VERSION 5.7 ;
BUSBITCHARS "[]" ;
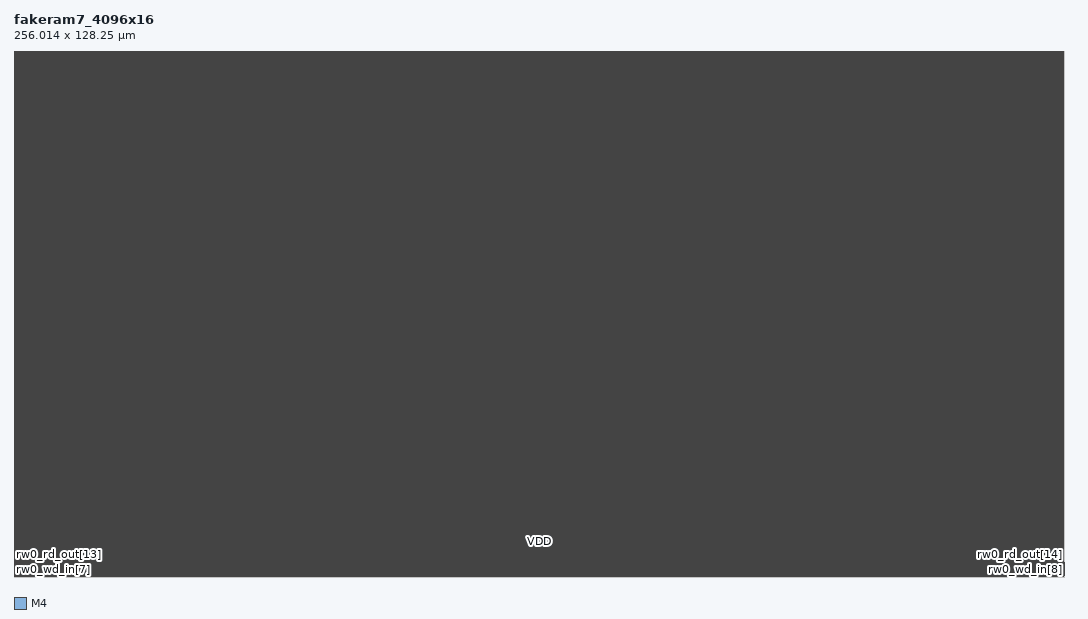
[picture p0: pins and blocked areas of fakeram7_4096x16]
MACRO fakeram7_4096x16
  FOREIGN fakeram7_4096x16 0 0 ;
  SYMMETRY X Y R90 ;
  SIZE 256.014 BY 128.250 ;
  CLASS BLOCK ;
  PIN rw0_clk
    DIRECTION INPUT ;
    USE SIGNAL ;
    SHAPE ABUTMENT ;
    PORT
      LAYER M4 ;
      RECT 0.000 0.276 0.072 0.300 ;
    END
  END rw0_clk
  PIN rw0_ce_in
    DIRECTION INPUT ;
    USE SIGNAL ;
    SHAPE ABUTMENT ;
    PORT
      LAYER M4 ;
      RECT 255.942 0.276 256.014 0.300 ;
    END
  END rw0_ce_in
  PIN rw0_we_in
    DIRECTION INPUT ;
    USE SIGNAL ;
    SHAPE ABUTMENT ;
    PORT
      LAYER M4 ;
      RECT 0.000 0.420 0.072 0.444 ;
    END
  END rw0_we_in
  PIN rw0_addr_in[0]
    DIRECTION INPUT ;
    USE SIGNAL ;
    SHAPE ABUTMENT ;
    PORT
      LAYER M4 ;
      RECT 255.942 0.420 256.014 0.444 ;
    END
  END rw0_addr_in[0]
  PIN rw0_addr_in[1]
    DIRECTION INPUT ;
    USE SIGNAL ;
    SHAPE ABUTMENT ;
    PORT
      LAYER M4 ;
      RECT 0.000 0.564 0.072 0.588 ;
    END
  END rw0_addr_in[1]
  PIN rw0_addr_in[2]
    DIRECTION INPUT ;
    USE SIGNAL ;
    SHAPE ABUTMENT ;
    PORT
      LAYER M4 ;
      RECT 255.942 0.564 256.014 0.588 ;
    END
  END rw0_addr_in[2]
  PIN rw0_addr_in[3]
    DIRECTION INPUT ;
    USE SIGNAL ;
    SHAPE ABUTMENT ;
    PORT
      LAYER M4 ;
      RECT 0.000 0.708 0.072 0.732 ;
    END
  END rw0_addr_in[3]
  PIN rw0_addr_in[4]
    DIRECTION INPUT ;
    USE SIGNAL ;
    SHAPE ABUTMENT ;
    PORT
      LAYER M4 ;
      RECT 255.942 0.708 256.014 0.732 ;
    END
  END rw0_addr_in[4]
  PIN rw0_addr_in[5]
    DIRECTION INPUT ;
    USE SIGNAL ;
    SHAPE ABUTMENT ;
    PORT
      LAYER M4 ;
      RECT 0.000 0.852 0.072 0.876 ;
    END
  END rw0_addr_in[5]
  PIN rw0_addr_in[6]
    DIRECTION INPUT ;
    USE SIGNAL ;
    SHAPE ABUTMENT ;
    PORT
      LAYER M4 ;
      RECT 255.942 0.852 256.014 0.876 ;
    END
  END rw0_addr_in[6]
  PIN rw0_addr_in[7]
    DIRECTION INPUT ;
    USE SIGNAL ;
    SHAPE ABUTMENT ;
    PORT
      LAYER M4 ;
      RECT 0.000 0.996 0.072 1.020 ;
    END
  END rw0_addr_in[7]
  PIN rw0_addr_in[8]
    DIRECTION INPUT ;
    USE SIGNAL ;
    SHAPE ABUTMENT ;
    PORT
      LAYER M4 ;
      RECT 255.942 0.996 256.014 1.020 ;
    END
  END rw0_addr_in[8]
  PIN rw0_addr_in[9]
    DIRECTION INPUT ;
    USE SIGNAL ;
    SHAPE ABUTMENT ;
    PORT
      LAYER M4 ;
      RECT 0.000 1.140 0.072 1.164 ;
    END
  END rw0_addr_in[9]
  PIN rw0_addr_in[10]
    DIRECTION INPUT ;
    USE SIGNAL ;
    SHAPE ABUTMENT ;
    PORT
      LAYER M4 ;
      RECT 255.942 1.140 256.014 1.164 ;
    END
  END rw0_addr_in[10]
  PIN rw0_addr_in[11]
    DIRECTION INPUT ;
    USE SIGNAL ;
    SHAPE ABUTMENT ;
    PORT
      LAYER M4 ;
      RECT 0.000 1.284 0.072 1.308 ;
    END
  END rw0_addr_in[11]
  PIN rw0_wd_in[0]
    DIRECTION INPUT ;
    USE SIGNAL ;
    SHAPE ABUTMENT ;
    PORT
      LAYER M4 ;
      RECT 255.942 1.284 256.014 1.308 ;
    END
  END rw0_wd_in[0]
  PIN rw0_wd_in[1]
    DIRECTION INPUT ;
    USE SIGNAL ;
    SHAPE ABUTMENT ;
    PORT
      LAYER M4 ;
      RECT 0.000 1.428 0.072 1.452 ;
    END
  END rw0_wd_in[1]
  PIN rw0_wd_in[2]
    DIRECTION INPUT ;
    USE SIGNAL ;
    SHAPE ABUTMENT ;
    PORT
      LAYER M4 ;
      RECT 255.942 1.428 256.014 1.452 ;
    END
  END rw0_wd_in[2]
  PIN rw0_wd_in[3]
    DIRECTION INPUT ;
    USE SIGNAL ;
    SHAPE ABUTMENT ;
    PORT
      LAYER M4 ;
      RECT 0.000 1.572 0.072 1.596 ;
    END
  END rw0_wd_in[3]
  PIN rw0_wd_in[4]
    DIRECTION INPUT ;
    USE SIGNAL ;
    SHAPE ABUTMENT ;
    PORT
      LAYER M4 ;
      RECT 255.942 1.572 256.014 1.596 ;
    END
  END rw0_wd_in[4]
  PIN rw0_wd_in[5]
    DIRECTION INPUT ;
    USE SIGNAL ;
    SHAPE ABUTMENT ;
    PORT
      LAYER M4 ;
      RECT 0.000 1.716 0.072 1.740 ;
    END
  END rw0_wd_in[5]
  PIN rw0_wd_in[6]
    DIRECTION INPUT ;
    USE SIGNAL ;
    SHAPE ABUTMENT ;
    PORT
      LAYER M4 ;
      RECT 255.942 1.716 256.014 1.740 ;
    END
  END rw0_wd_in[6]
  PIN rw0_wd_in[7]
    DIRECTION INPUT ;
    USE SIGNAL ;
    SHAPE ABUTMENT ;
    PORT
      LAYER M4 ;
      RECT 0.000 1.860 0.072 1.884 ;
    END
  END rw0_wd_in[7]
  PIN rw0_wd_in[8]
    DIRECTION INPUT ;
    USE SIGNAL ;
    SHAPE ABUTMENT ;
    PORT
      LAYER M4 ;
      RECT 255.942 1.860 256.014 1.884 ;
    END
  END rw0_wd_in[8]
  PIN rw0_wd_in[9]
    DIRECTION INPUT ;
    USE SIGNAL ;
    SHAPE ABUTMENT ;
    PORT
      LAYER M4 ;
      RECT 0.000 2.004 0.072 2.028 ;
    END
  END rw0_wd_in[9]
  PIN rw0_wd_in[10]
    DIRECTION INPUT ;
    USE SIGNAL ;
    SHAPE ABUTMENT ;
    PORT
      LAYER M4 ;
      RECT 255.942 2.004 256.014 2.028 ;
    END
  END rw0_wd_in[10]
  PIN rw0_wd_in[11]
    DIRECTION INPUT ;
    USE SIGNAL ;
    SHAPE ABUTMENT ;
    PORT
      LAYER M4 ;
      RECT 0.000 2.148 0.072 2.172 ;
    END
  END rw0_wd_in[11]
  PIN rw0_wd_in[12]
    DIRECTION INPUT ;
    USE SIGNAL ;
    SHAPE ABUTMENT ;
    PORT
      LAYER M4 ;
      RECT 255.942 2.148 256.014 2.172 ;
    END
  END rw0_wd_in[12]
  PIN rw0_wd_in[13]
    DIRECTION INPUT ;
    USE SIGNAL ;
    SHAPE ABUTMENT ;
    PORT
      LAYER M4 ;
      RECT 0.000 2.292 0.072 2.316 ;
    END
  END rw0_wd_in[13]
  PIN rw0_wd_in[14]
    DIRECTION INPUT ;
    USE SIGNAL ;
    SHAPE ABUTMENT ;
    PORT
      LAYER M4 ;
      RECT 255.942 2.292 256.014 2.316 ;
    END
  END rw0_wd_in[14]
  PIN rw0_wd_in[15]
    DIRECTION INPUT ;
    USE SIGNAL ;
    SHAPE ABUTMENT ;
    PORT
      LAYER M4 ;
      RECT 0.000 2.436 0.072 2.460 ;
    END
  END rw0_wd_in[15]
  PIN rw0_rd_out[0]
    DIRECTION OUTPUT ;
    USE SIGNAL ;
    SHAPE ABUTMENT ;
    PORT
      LAYER M4 ;
      RECT 255.942 2.436 256.014 2.460 ;
    END
  END rw0_rd_out[0]
  PIN rw0_rd_out[1]
    DIRECTION OUTPUT ;
    USE SIGNAL ;
    SHAPE ABUTMENT ;
    PORT
      LAYER M4 ;
      RECT 0.000 2.580 0.072 2.604 ;
    END
  END rw0_rd_out[1]
  PIN rw0_rd_out[2]
    DIRECTION OUTPUT ;
    USE SIGNAL ;
    SHAPE ABUTMENT ;
    PORT
      LAYER M4 ;
      RECT 255.942 2.580 256.014 2.604 ;
    END
  END rw0_rd_out[2]
  PIN rw0_rd_out[3]
    DIRECTION OUTPUT ;
    USE SIGNAL ;
    SHAPE ABUTMENT ;
    PORT
      LAYER M4 ;
      RECT 0.000 2.724 0.072 2.748 ;
    END
  END rw0_rd_out[3]
  PIN rw0_rd_out[4]
    DIRECTION OUTPUT ;
    USE SIGNAL ;
    SHAPE ABUTMENT ;
    PORT
      LAYER M4 ;
      RECT 255.942 2.724 256.014 2.748 ;
    END
  END rw0_rd_out[4]
  PIN rw0_rd_out[5]
    DIRECTION OUTPUT ;
    USE SIGNAL ;
    SHAPE ABUTMENT ;
    PORT
      LAYER M4 ;
      RECT 0.000 2.868 0.072 2.892 ;
    END
  END rw0_rd_out[5]
  PIN rw0_rd_out[6]
    DIRECTION OUTPUT ;
    USE SIGNAL ;
    SHAPE ABUTMENT ;
    PORT
      LAYER M4 ;
      RECT 255.942 2.868 256.014 2.892 ;
    END
  END rw0_rd_out[6]
  PIN rw0_rd_out[7]
    DIRECTION OUTPUT ;
    USE SIGNAL ;
    SHAPE ABUTMENT ;
    PORT
      LAYER M4 ;
      RECT 0.000 3.012 0.072 3.036 ;
    END
  END rw0_rd_out[7]
  PIN rw0_rd_out[8]
    DIRECTION OUTPUT ;
    USE SIGNAL ;
    SHAPE ABUTMENT ;
    PORT
      LAYER M4 ;
      RECT 255.942 3.012 256.014 3.036 ;
    END
  END rw0_rd_out[8]
  PIN rw0_rd_out[9]
    DIRECTION OUTPUT ;
    USE SIGNAL ;
    SHAPE ABUTMENT ;
    PORT
      LAYER M4 ;
      RECT 0.000 3.156 0.072 3.180 ;
    END
  END rw0_rd_out[9]
  PIN rw0_rd_out[10]
    DIRECTION OUTPUT ;
    USE SIGNAL ;
    SHAPE ABUTMENT ;
    PORT
      LAYER M4 ;
      RECT 255.942 3.156 256.014 3.180 ;
    END
  END rw0_rd_out[10]
  PIN rw0_rd_out[11]
    DIRECTION OUTPUT ;
    USE SIGNAL ;
    SHAPE ABUTMENT ;
    PORT
      LAYER M4 ;
      RECT 0.000 3.300 0.072 3.324 ;
    END
  END rw0_rd_out[11]
  PIN rw0_rd_out[12]
    DIRECTION OUTPUT ;
    USE SIGNAL ;
    SHAPE ABUTMENT ;
    PORT
      LAYER M4 ;
      RECT 255.942 3.300 256.014 3.324 ;
    END
  END rw0_rd_out[12]
  PIN rw0_rd_out[13]
    DIRECTION OUTPUT ;
    USE SIGNAL ;
    SHAPE ABUTMENT ;
    PORT
      LAYER M4 ;
      RECT 0.000 3.444 0.072 3.468 ;
    END
  END rw0_rd_out[13]
  PIN rw0_rd_out[14]
    DIRECTION OUTPUT ;
    USE SIGNAL ;
    SHAPE ABUTMENT ;
    PORT
      LAYER M4 ;
      RECT 255.942 3.444 256.014 3.468 ;
    END
  END rw0_rd_out[14]
  PIN rw0_rd_out[15]
    DIRECTION OUTPUT ;
    USE SIGNAL ;
    SHAPE ABUTMENT ;
    PORT
      LAYER M4 ;
      RECT 0.000 3.588 0.072 3.612 ;
    END
  END rw0_rd_out[15]
  PIN VDD
    DIRECTION INOUT ;
    USE POWER ;
    PORT
      LAYER M4 ;
      RECT 0.054 0.012 255.960 0.036 ;
      RECT 0.054 0.108 255.960 0.132 ;
      RECT 0.054 0.204 255.960 0.228 ;
      RECT 0.054 0.300 255.960 0.324 ;
      RECT 0.054 0.396 255.960 0.420 ;
      RECT 0.054 0.492 255.960 0.516 ;
      RECT 0.054 0.588 255.960 0.612 ;
      RECT 0.054 0.684 255.960 0.708 ;
      RECT 0.054 0.780 255.960 0.804 ;
      RECT 0.054 0.876 255.960 0.900 ;
      RECT 0.054 0.972 255.960 0.996 ;
      RECT 0.054 1.068 255.960 1.092 ;
      RECT 0.054 1.164 255.960 1.188 ;
      RECT 0.054 1.260 255.960 1.284 ;
      RECT 0.054 1.356 255.960 1.380 ;
      RECT 0.054 1.452 255.960 1.476 ;
      RECT 0.054 1.548 255.960 1.572 ;
      RECT 0.054 1.644 255.960 1.668 ;
      RECT 0.054 1.740 255.960 1.764 ;
      RECT 0.054 1.836 255.960 1.860 ;
      RECT 0.054 1.932 255.960 1.956 ;
      RECT 0.054 2.028 255.960 2.052 ;
      RECT 0.054 2.124 255.960 2.148 ;
      RECT 0.054 2.220 255.960 2.244 ;
      RECT 0.054 2.316 255.960 2.340 ;
      RECT 0.054 2.412 255.960 2.436 ;
      RECT 0.054 2.508 255.960 2.532 ;
      RECT 0.054 2.604 255.960 2.628 ;
      RECT 0.054 2.700 255.960 2.724 ;
      RECT 0.054 2.796 255.960 2.820 ;
      RECT 0.054 2.892 255.960 2.916 ;
      RECT 0.054 2.988 255.960 3.012 ;
      RECT 0.054 3.084 255.960 3.108 ;
      RECT 0.054 3.180 255.960 3.204 ;
      RECT 0.054 3.276 255.960 3.300 ;
      RECT 0.054 3.372 255.960 3.396 ;
      RECT 0.054 3.468 255.960 3.492 ;
      RECT 0.054 3.564 255.960 3.588 ;
      RECT 0.054 3.660 255.960 3.684 ;
      RECT 0.054 3.756 255.960 3.780 ;
      RECT 0.054 3.852 255.960 3.876 ;
      RECT 0.054 3.948 255.960 3.972 ;
      RECT 0.054 4.044 255.960 4.068 ;
      RECT 0.054 4.140 255.960 4.164 ;
      RECT 0.054 4.236 255.960 4.260 ;
      RECT 0.054 4.332 255.960 4.356 ;
      RECT 0.054 4.428 255.960 4.452 ;
      RECT 0.054 4.524 255.960 4.548 ;
      RECT 0.054 4.620 255.960 4.644 ;
      RECT 0.054 4.716 255.960 4.740 ;
      RECT 0.054 4.812 255.960 4.836 ;
      RECT 0.054 4.908 255.960 4.932 ;
      RECT 0.054 5.004 255.960 5.028 ;
      RECT 0.054 5.100 255.960 5.124 ;
      RECT 0.054 5.196 255.960 5.220 ;
      RECT 0.054 5.292 255.960 5.316 ;
      RECT 0.054 5.388 255.960 5.412 ;
      RECT 0.054 5.484 255.960 5.508 ;
      RECT 0.054 5.580 255.960 5.604 ;
      RECT 0.054 5.676 255.960 5.700 ;
      RECT 0.054 5.772 255.960 5.796 ;
      RECT 0.054 5.868 255.960 5.892 ;
      RECT 0.054 5.964 255.960 5.988 ;
      RECT 0.054 6.060 255.960 6.084 ;
      RECT 0.054 6.156 255.960 6.180 ;
      RECT 0.054 6.252 255.960 6.276 ;
      RECT 0.054 6.348 255.960 6.372 ;
      RECT 0.054 6.444 255.960 6.468 ;
      RECT 0.054 6.540 255.960 6.564 ;
      RECT 0.054 6.636 255.960 6.660 ;
      RECT 0.054 6.732 255.960 6.756 ;
      RECT 0.054 6.828 255.960 6.852 ;
      RECT 0.054 6.924 255.960 6.948 ;
      RECT 0.054 7.020 255.960 7.044 ;
      RECT 0.054 7.116 255.960 7.140 ;
      RECT 0.054 7.212 255.960 7.236 ;
      RECT 0.054 7.308 255.960 7.332 ;
      RECT 0.054 7.404 255.960 7.428 ;
      RECT 0.054 7.500 255.960 7.524 ;
      RECT 0.054 7.596 255.960 7.620 ;
      RECT 0.054 7.692 255.960 7.716 ;
      RECT 0.054 7.788 255.960 7.812 ;
      RECT 0.054 7.884 255.960 7.908 ;
      RECT 0.054 7.980 255.960 8.004 ;
      RECT 0.054 8.076 255.960 8.100 ;
      RECT 0.054 8.172 255.960 8.196 ;
      RECT 0.054 8.268 255.960 8.292 ;
      RECT 0.054 8.364 255.960 8.388 ;
      RECT 0.054 8.460 255.960 8.484 ;
      RECT 0.054 8.556 255.960 8.580 ;
      RECT 0.054 8.652 255.960 8.676 ;
      RECT 0.054 8.748 255.960 8.772 ;
      RECT 0.054 8.844 255.960 8.868 ;
      RECT 0.054 8.940 255.960 8.964 ;
      RECT 0.054 9.036 255.960 9.060 ;
      RECT 0.054 9.132 255.960 9.156 ;
      RECT 0.054 9.228 255.960 9.252 ;
      RECT 0.054 9.324 255.960 9.348 ;
      RECT 0.054 9.420 255.960 9.444 ;
      RECT 0.054 9.516 255.960 9.540 ;
      RECT 0.054 9.612 255.960 9.636 ;
      RECT 0.054 9.708 255.960 9.732 ;
      RECT 0.054 9.804 255.960 9.828 ;
      RECT 0.054 9.900 255.960 9.924 ;
      RECT 0.054 9.996 255.960 10.020 ;
      RECT 0.054 10.092 255.960 10.116 ;
      RECT 0.054 10.188 255.960 10.212 ;
      RECT 0.054 10.284 255.960 10.308 ;
      RECT 0.054 10.380 255.960 10.404 ;
      RECT 0.054 10.476 255.960 10.500 ;
      RECT 0.054 10.572 255.960 10.596 ;
      RECT 0.054 10.668 255.960 10.692 ;
      RECT 0.054 10.764 255.960 10.788 ;
      RECT 0.054 10.860 255.960 10.884 ;
      RECT 0.054 10.956 255.960 10.980 ;
      RECT 0.054 11.052 255.960 11.076 ;
      RECT 0.054 11.148 255.960 11.172 ;
      RECT 0.054 11.244 255.960 11.268 ;
      RECT 0.054 11.340 255.960 11.364 ;
      RECT 0.054 11.436 255.960 11.460 ;
      RECT 0.054 11.532 255.960 11.556 ;
      RECT 0.054 11.628 255.960 11.652 ;
      RECT 0.054 11.724 255.960 11.748 ;
      RECT 0.054 11.820 255.960 11.844 ;
      RECT 0.054 11.916 255.960 11.940 ;
      RECT 0.054 12.012 255.960 12.036 ;
      RECT 0.054 12.108 255.960 12.132 ;
      RECT 0.054 12.204 255.960 12.228 ;
      RECT 0.054 12.300 255.960 12.324 ;
      RECT 0.054 12.396 255.960 12.420 ;
      RECT 0.054 12.492 255.960 12.516 ;
      RECT 0.054 12.588 255.960 12.612 ;
      RECT 0.054 12.684 255.960 12.708 ;
      RECT 0.054 12.780 255.960 12.804 ;
      RECT 0.054 12.876 255.960 12.900 ;
      RECT 0.054 12.972 255.960 12.996 ;
      RECT 0.054 13.068 255.960 13.092 ;
      RECT 0.054 13.164 255.960 13.188 ;
      RECT 0.054 13.260 255.960 13.284 ;
      RECT 0.054 13.356 255.960 13.380 ;
      RECT 0.054 13.452 255.960 13.476 ;
      RECT 0.054 13.548 255.960 13.572 ;
      RECT 0.054 13.644 255.960 13.668 ;
      RECT 0.054 13.740 255.960 13.764 ;
      RECT 0.054 13.836 255.960 13.860 ;
      RECT 0.054 13.932 255.960 13.956 ;
      RECT 0.054 14.028 255.960 14.052 ;
      RECT 0.054 14.124 255.960 14.148 ;
      RECT 0.054 14.220 255.960 14.244 ;
      RECT 0.054 14.316 255.960 14.340 ;
      RECT 0.054 14.412 255.960 14.436 ;
      RECT 0.054 14.508 255.960 14.532 ;
      RECT 0.054 14.604 255.960 14.628 ;
      RECT 0.054 14.700 255.960 14.724 ;
      RECT 0.054 14.796 255.960 14.820 ;
      RECT 0.054 14.892 255.960 14.916 ;
      RECT 0.054 14.988 255.960 15.012 ;
      RECT 0.054 15.084 255.960 15.108 ;
      RECT 0.054 15.180 255.960 15.204 ;
      RECT 0.054 15.276 255.960 15.300 ;
      RECT 0.054 15.372 255.960 15.396 ;
      RECT 0.054 15.468 255.960 15.492 ;
      RECT 0.054 15.564 255.960 15.588 ;
      RECT 0.054 15.660 255.960 15.684 ;
      RECT 0.054 15.756 255.960 15.780 ;
      RECT 0.054 15.852 255.960 15.876 ;
      RECT 0.054 15.948 255.960 15.972 ;
      RECT 0.054 16.044 255.960 16.068 ;
      RECT 0.054 16.140 255.960 16.164 ;
      RECT 0.054 16.236 255.960 16.260 ;
      RECT 0.054 16.332 255.960 16.356 ;
      RECT 0.054 16.428 255.960 16.452 ;
      RECT 0.054 16.524 255.960 16.548 ;
      RECT 0.054 16.620 255.960 16.644 ;
      RECT 0.054 16.716 255.960 16.740 ;
      RECT 0.054 16.812 255.960 16.836 ;
      RECT 0.054 16.908 255.960 16.932 ;
      RECT 0.054 17.004 255.960 17.028 ;
      RECT 0.054 17.100 255.960 17.124 ;
      RECT 0.054 17.196 255.960 17.220 ;
      RECT 0.054 17.292 255.960 17.316 ;
      RECT 0.054 17.388 255.960 17.412 ;
      RECT 0.054 17.484 255.960 17.508 ;
      RECT 0.054 17.580 255.960 17.604 ;
      RECT 0.054 17.676 255.960 17.700 ;
      RECT 0.054 17.772 255.960 17.796 ;
      RECT 0.054 17.868 255.960 17.892 ;
      RECT 0.054 17.964 255.960 17.988 ;
      RECT 0.054 18.060 255.960 18.084 ;
      RECT 0.054 18.156 255.960 18.180 ;
      RECT 0.054 18.252 255.960 18.276 ;
      RECT 0.054 18.348 255.960 18.372 ;
      RECT 0.054 18.444 255.960 18.468 ;
      RECT 0.054 18.540 255.960 18.564 ;
      RECT 0.054 18.636 255.960 18.660 ;
      RECT 0.054 18.732 255.960 18.756 ;
      RECT 0.054 18.828 255.960 18.852 ;
      RECT 0.054 18.924 255.960 18.948 ;
      RECT 0.054 19.020 255.960 19.044 ;
      RECT 0.054 19.116 255.960 19.140 ;
      RECT 0.054 19.212 255.960 19.236 ;
      RECT 0.054 19.308 255.960 19.332 ;
      RECT 0.054 19.404 255.960 19.428 ;
      RECT 0.054 19.500 255.960 19.524 ;
      RECT 0.054 19.596 255.960 19.620 ;
      RECT 0.054 19.692 255.960 19.716 ;
      RECT 0.054 19.788 255.960 19.812 ;
      RECT 0.054 19.884 255.960 19.908 ;
      RECT 0.054 19.980 255.960 20.004 ;
      RECT 0.054 20.076 255.960 20.100 ;
      RECT 0.054 20.172 255.960 20.196 ;
      RECT 0.054 20.268 255.960 20.292 ;
      RECT 0.054 20.364 255.960 20.388 ;
      RECT 0.054 20.460 255.960 20.484 ;
      RECT 0.054 20.556 255.960 20.580 ;
      RECT 0.054 20.652 255.960 20.676 ;
      RECT 0.054 20.748 255.960 20.772 ;
      RECT 0.054 20.844 255.960 20.868 ;
      RECT 0.054 20.940 255.960 20.964 ;
      RECT 0.054 21.036 255.960 21.060 ;
      RECT 0.054 21.132 255.960 21.156 ;
      RECT 0.054 21.228 255.960 21.252 ;
      RECT 0.054 21.324 255.960 21.348 ;
      RECT 0.054 21.420 255.960 21.444 ;
      RECT 0.054 21.516 255.960 21.540 ;
      RECT 0.054 21.612 255.960 21.636 ;
      RECT 0.054 21.708 255.960 21.732 ;
      RECT 0.054 21.804 255.960 21.828 ;
      RECT 0.054 21.900 255.960 21.924 ;
      RECT 0.054 21.996 255.960 22.020 ;
      RECT 0.054 22.092 255.960 22.116 ;
      RECT 0.054 22.188 255.960 22.212 ;
      RECT 0.054 22.284 255.960 22.308 ;
      RECT 0.054 22.380 255.960 22.404 ;
      RECT 0.054 22.476 255.960 22.500 ;
      RECT 0.054 22.572 255.960 22.596 ;
      RECT 0.054 22.668 255.960 22.692 ;
      RECT 0.054 22.764 255.960 22.788 ;
      RECT 0.054 22.860 255.960 22.884 ;
      RECT 0.054 22.956 255.960 22.980 ;
      RECT 0.054 23.052 255.960 23.076 ;
      RECT 0.054 23.148 255.960 23.172 ;
      RECT 0.054 23.244 255.960 23.268 ;
      RECT 0.054 23.340 255.960 23.364 ;
      RECT 0.054 23.436 255.960 23.460 ;
      RECT 0.054 23.532 255.960 23.556 ;
      RECT 0.054 23.628 255.960 23.652 ;
      RECT 0.054 23.724 255.960 23.748 ;
      RECT 0.054 23.820 255.960 23.844 ;
      RECT 0.054 23.916 255.960 23.940 ;
      RECT 0.054 24.012 255.960 24.036 ;
      RECT 0.054 24.108 255.960 24.132 ;
      RECT 0.054 24.204 255.960 24.228 ;
      RECT 0.054 24.300 255.960 24.324 ;
      RECT 0.054 24.396 255.960 24.420 ;
      RECT 0.054 24.492 255.960 24.516 ;
      RECT 0.054 24.588 255.960 24.612 ;
      RECT 0.054 24.684 255.960 24.708 ;
      RECT 0.054 24.780 255.960 24.804 ;
      RECT 0.054 24.876 255.960 24.900 ;
      RECT 0.054 24.972 255.960 24.996 ;
      RECT 0.054 25.068 255.960 25.092 ;
      RECT 0.054 25.164 255.960 25.188 ;
      RECT 0.054 25.260 255.960 25.284 ;
      RECT 0.054 25.356 255.960 25.380 ;
      RECT 0.054 25.452 255.960 25.476 ;
      RECT 0.054 25.548 255.960 25.572 ;
      RECT 0.054 25.644 255.960 25.668 ;
      RECT 0.054 25.740 255.960 25.764 ;
      RECT 0.054 25.836 255.960 25.860 ;
      RECT 0.054 25.932 255.960 25.956 ;
      RECT 0.054 26.028 255.960 26.052 ;
      RECT 0.054 26.124 255.960 26.148 ;
      RECT 0.054 26.220 255.960 26.244 ;
      RECT 0.054 26.316 255.960 26.340 ;
      RECT 0.054 26.412 255.960 26.436 ;
      RECT 0.054 26.508 255.960 26.532 ;
      RECT 0.054 26.604 255.960 26.628 ;
      RECT 0.054 26.700 255.960 26.724 ;
      RECT 0.054 26.796 255.960 26.820 ;
      RECT 0.054 26.892 255.960 26.916 ;
      RECT 0.054 26.988 255.960 27.012 ;
      RECT 0.054 27.084 255.960 27.108 ;
      RECT 0.054 27.180 255.960 27.204 ;
      RECT 0.054 27.276 255.960 27.300 ;
      RECT 0.054 27.372 255.960 27.396 ;
      RECT 0.054 27.468 255.960 27.492 ;
      RECT 0.054 27.564 255.960 27.588 ;
      RECT 0.054 27.660 255.960 27.684 ;
      RECT 0.054 27.756 255.960 27.780 ;
      RECT 0.054 27.852 255.960 27.876 ;
      RECT 0.054 27.948 255.960 27.972 ;
      RECT 0.054 28.044 255.960 28.068 ;
      RECT 0.054 28.140 255.960 28.164 ;
      RECT 0.054 28.236 255.960 28.260 ;
      RECT 0.054 28.332 255.960 28.356 ;
      RECT 0.054 28.428 255.960 28.452 ;
      RECT 0.054 28.524 255.960 28.548 ;
      RECT 0.054 28.620 255.960 28.644 ;
      RECT 0.054 28.716 255.960 28.740 ;
      RECT 0.054 28.812 255.960 28.836 ;
      RECT 0.054 28.908 255.960 28.932 ;
      RECT 0.054 29.004 255.960 29.028 ;
      RECT 0.054 29.100 255.960 29.124 ;
      RECT 0.054 29.196 255.960 29.220 ;
      RECT 0.054 29.292 255.960 29.316 ;
      RECT 0.054 29.388 255.960 29.412 ;
      RECT 0.054 29.484 255.960 29.508 ;
      RECT 0.054 29.580 255.960 29.604 ;
      RECT 0.054 29.676 255.960 29.700 ;
      RECT 0.054 29.772 255.960 29.796 ;
      RECT 0.054 29.868 255.960 29.892 ;
      RECT 0.054 29.964 255.960 29.988 ;
      RECT 0.054 30.060 255.960 30.084 ;
      RECT 0.054 30.156 255.960 30.180 ;
      RECT 0.054 30.252 255.960 30.276 ;
      RECT 0.054 30.348 255.960 30.372 ;
      RECT 0.054 30.444 255.960 30.468 ;
      RECT 0.054 30.540 255.960 30.564 ;
      RECT 0.054 30.636 255.960 30.660 ;
      RECT 0.054 30.732 255.960 30.756 ;
      RECT 0.054 30.828 255.960 30.852 ;
      RECT 0.054 30.924 255.960 30.948 ;
      RECT 0.054 31.020 255.960 31.044 ;
      RECT 0.054 31.116 255.960 31.140 ;
      RECT 0.054 31.212 255.960 31.236 ;
      RECT 0.054 31.308 255.960 31.332 ;
      RECT 0.054 31.404 255.960 31.428 ;
      RECT 0.054 31.500 255.960 31.524 ;
      RECT 0.054 31.596 255.960 31.620 ;
      RECT 0.054 31.692 255.960 31.716 ;
      RECT 0.054 31.788 255.960 31.812 ;
      RECT 0.054 31.884 255.960 31.908 ;
      RECT 0.054 31.980 255.960 32.004 ;
      RECT 0.054 32.076 255.960 32.100 ;
      RECT 0.054 32.172 255.960 32.196 ;
      RECT 0.054 32.268 255.960 32.292 ;
      RECT 0.054 32.364 255.960 32.388 ;
      RECT 0.054 32.460 255.960 32.484 ;
      RECT 0.054 32.556 255.960 32.580 ;
      RECT 0.054 32.652 255.960 32.676 ;
      RECT 0.054 32.748 255.960 32.772 ;
      RECT 0.054 32.844 255.960 32.868 ;
      RECT 0.054 32.940 255.960 32.964 ;
      RECT 0.054 33.036 255.960 33.060 ;
      RECT 0.054 33.132 255.960 33.156 ;
      RECT 0.054 33.228 255.960 33.252 ;
      RECT 0.054 33.324 255.960 33.348 ;
      RECT 0.054 33.420 255.960 33.444 ;
      RECT 0.054 33.516 255.960 33.540 ;
      RECT 0.054 33.612 255.960 33.636 ;
      RECT 0.054 33.708 255.960 33.732 ;
      RECT 0.054 33.804 255.960 33.828 ;
      RECT 0.054 33.900 255.960 33.924 ;
      RECT 0.054 33.996 255.960 34.020 ;
      RECT 0.054 34.092 255.960 34.116 ;
      RECT 0.054 34.188 255.960 34.212 ;
      RECT 0.054 34.284 255.960 34.308 ;
      RECT 0.054 34.380 255.960 34.404 ;
      RECT 0.054 34.476 255.960 34.500 ;
      RECT 0.054 34.572 255.960 34.596 ;
      RECT 0.054 34.668 255.960 34.692 ;
      RECT 0.054 34.764 255.960 34.788 ;
      RECT 0.054 34.860 255.960 34.884 ;
      RECT 0.054 34.956 255.960 34.980 ;
      RECT 0.054 35.052 255.960 35.076 ;
      RECT 0.054 35.148 255.960 35.172 ;
      RECT 0.054 35.244 255.960 35.268 ;
      RECT 0.054 35.340 255.960 35.364 ;
      RECT 0.054 35.436 255.960 35.460 ;
      RECT 0.054 35.532 255.960 35.556 ;
      RECT 0.054 35.628 255.960 35.652 ;
      RECT 0.054 35.724 255.960 35.748 ;
      RECT 0.054 35.820 255.960 35.844 ;
      RECT 0.054 35.916 255.960 35.940 ;
      RECT 0.054 36.012 255.960 36.036 ;
      RECT 0.054 36.108 255.960 36.132 ;
      RECT 0.054 36.204 255.960 36.228 ;
      RECT 0.054 36.300 255.960 36.324 ;
      RECT 0.054 36.396 255.960 36.420 ;
      RECT 0.054 36.492 255.960 36.516 ;
      RECT 0.054 36.588 255.960 36.612 ;
      RECT 0.054 36.684 255.960 36.708 ;
      RECT 0.054 36.780 255.960 36.804 ;
      RECT 0.054 36.876 255.960 36.900 ;
      RECT 0.054 36.972 255.960 36.996 ;
      RECT 0.054 37.068 255.960 37.092 ;
      RECT 0.054 37.164 255.960 37.188 ;
      RECT 0.054 37.260 255.960 37.284 ;
      RECT 0.054 37.356 255.960 37.380 ;
      RECT 0.054 37.452 255.960 37.476 ;
      RECT 0.054 37.548 255.960 37.572 ;
      RECT 0.054 37.644 255.960 37.668 ;
      RECT 0.054 37.740 255.960 37.764 ;
      RECT 0.054 37.836 255.960 37.860 ;
      RECT 0.054 37.932 255.960 37.956 ;
      RECT 0.054 38.028 255.960 38.052 ;
      RECT 0.054 38.124 255.960 38.148 ;
      RECT 0.054 38.220 255.960 38.244 ;
      RECT 0.054 38.316 255.960 38.340 ;
      RECT 0.054 38.412 255.960 38.436 ;
      RECT 0.054 38.508 255.960 38.532 ;
      RECT 0.054 38.604 255.960 38.628 ;
      RECT 0.054 38.700 255.960 38.724 ;
      RECT 0.054 38.796 255.960 38.820 ;
      RECT 0.054 38.892 255.960 38.916 ;
      RECT 0.054 38.988 255.960 39.012 ;
      RECT 0.054 39.084 255.960 39.108 ;
      RECT 0.054 39.180 255.960 39.204 ;
      RECT 0.054 39.276 255.960 39.300 ;
      RECT 0.054 39.372 255.960 39.396 ;
      RECT 0.054 39.468 255.960 39.492 ;
      RECT 0.054 39.564 255.960 39.588 ;
      RECT 0.054 39.660 255.960 39.684 ;
      RECT 0.054 39.756 255.960 39.780 ;
      RECT 0.054 39.852 255.960 39.876 ;
      RECT 0.054 39.948 255.960 39.972 ;
      RECT 0.054 40.044 255.960 40.068 ;
      RECT 0.054 40.140 255.960 40.164 ;
      RECT 0.054 40.236 255.960 40.260 ;
      RECT 0.054 40.332 255.960 40.356 ;
      RECT 0.054 40.428 255.960 40.452 ;
      RECT 0.054 40.524 255.960 40.548 ;
      RECT 0.054 40.620 255.960 40.644 ;
      RECT 0.054 40.716 255.960 40.740 ;
      RECT 0.054 40.812 255.960 40.836 ;
      RECT 0.054 40.908 255.960 40.932 ;
      RECT 0.054 41.004 255.960 41.028 ;
      RECT 0.054 41.100 255.960 41.124 ;
      RECT 0.054 41.196 255.960 41.220 ;
      RECT 0.054 41.292 255.960 41.316 ;
      RECT 0.054 41.388 255.960 41.412 ;
      RECT 0.054 41.484 255.960 41.508 ;
      RECT 0.054 41.580 255.960 41.604 ;
      RECT 0.054 41.676 255.960 41.700 ;
      RECT 0.054 41.772 255.960 41.796 ;
      RECT 0.054 41.868 255.960 41.892 ;
      RECT 0.054 41.964 255.960 41.988 ;
      RECT 0.054 42.060 255.960 42.084 ;
      RECT 0.054 42.156 255.960 42.180 ;
      RECT 0.054 42.252 255.960 42.276 ;
      RECT 0.054 42.348 255.960 42.372 ;
      RECT 0.054 42.444 255.960 42.468 ;
      RECT 0.054 42.540 255.960 42.564 ;
      RECT 0.054 42.636 255.960 42.660 ;
      RECT 0.054 42.732 255.960 42.756 ;
      RECT 0.054 42.828 255.960 42.852 ;
      RECT 0.054 42.924 255.960 42.948 ;
      RECT 0.054 43.020 255.960 43.044 ;
      RECT 0.054 43.116 255.960 43.140 ;
      RECT 0.054 43.212 255.960 43.236 ;
      RECT 0.054 43.308 255.960 43.332 ;
      RECT 0.054 43.404 255.960 43.428 ;
      RECT 0.054 43.500 255.960 43.524 ;
      RECT 0.054 43.596 255.960 43.620 ;
      RECT 0.054 43.692 255.960 43.716 ;
      RECT 0.054 43.788 255.960 43.812 ;
      RECT 0.054 43.884 255.960 43.908 ;
      RECT 0.054 43.980 255.960 44.004 ;
      RECT 0.054 44.076 255.960 44.100 ;
      RECT 0.054 44.172 255.960 44.196 ;
      RECT 0.054 44.268 255.960 44.292 ;
      RECT 0.054 44.364 255.960 44.388 ;
      RECT 0.054 44.460 255.960 44.484 ;
      RECT 0.054 44.556 255.960 44.580 ;
      RECT 0.054 44.652 255.960 44.676 ;
      RECT 0.054 44.748 255.960 44.772 ;
      RECT 0.054 44.844 255.960 44.868 ;
      RECT 0.054 44.940 255.960 44.964 ;
      RECT 0.054 45.036 255.960 45.060 ;
      RECT 0.054 45.132 255.960 45.156 ;
      RECT 0.054 45.228 255.960 45.252 ;
      RECT 0.054 45.324 255.960 45.348 ;
      RECT 0.054 45.420 255.960 45.444 ;
      RECT 0.054 45.516 255.960 45.540 ;
      RECT 0.054 45.612 255.960 45.636 ;
      RECT 0.054 45.708 255.960 45.732 ;
      RECT 0.054 45.804 255.960 45.828 ;
      RECT 0.054 45.900 255.960 45.924 ;
      RECT 0.054 45.996 255.960 46.020 ;
      RECT 0.054 46.092 255.960 46.116 ;
      RECT 0.054 46.188 255.960 46.212 ;
      RECT 0.054 46.284 255.960 46.308 ;
      RECT 0.054 46.380 255.960 46.404 ;
      RECT 0.054 46.476 255.960 46.500 ;
      RECT 0.054 46.572 255.960 46.596 ;
      RECT 0.054 46.668 255.960 46.692 ;
      RECT 0.054 46.764 255.960 46.788 ;
      RECT 0.054 46.860 255.960 46.884 ;
      RECT 0.054 46.956 255.960 46.980 ;
      RECT 0.054 47.052 255.960 47.076 ;
      RECT 0.054 47.148 255.960 47.172 ;
      RECT 0.054 47.244 255.960 47.268 ;
      RECT 0.054 47.340 255.960 47.364 ;
      RECT 0.054 47.436 255.960 47.460 ;
      RECT 0.054 47.532 255.960 47.556 ;
      RECT 0.054 47.628 255.960 47.652 ;
      RECT 0.054 47.724 255.960 47.748 ;
      RECT 0.054 47.820 255.960 47.844 ;
      RECT 0.054 47.916 255.960 47.940 ;
      RECT 0.054 48.012 255.960 48.036 ;
      RECT 0.054 48.108 255.960 48.132 ;
      RECT 0.054 48.204 255.960 48.228 ;
      RECT 0.054 48.300 255.960 48.324 ;
      RECT 0.054 48.396 255.960 48.420 ;
      RECT 0.054 48.492 255.960 48.516 ;
      RECT 0.054 48.588 255.960 48.612 ;
      RECT 0.054 48.684 255.960 48.708 ;
      RECT 0.054 48.780 255.960 48.804 ;
      RECT 0.054 48.876 255.960 48.900 ;
      RECT 0.054 48.972 255.960 48.996 ;
      RECT 0.054 49.068 255.960 49.092 ;
      RECT 0.054 49.164 255.960 49.188 ;
      RECT 0.054 49.260 255.960 49.284 ;
      RECT 0.054 49.356 255.960 49.380 ;
      RECT 0.054 49.452 255.960 49.476 ;
      RECT 0.054 49.548 255.960 49.572 ;
      RECT 0.054 49.644 255.960 49.668 ;
      RECT 0.054 49.740 255.960 49.764 ;
      RECT 0.054 49.836 255.960 49.860 ;
      RECT 0.054 49.932 255.960 49.956 ;
      RECT 0.054 50.028 255.960 50.052 ;
      RECT 0.054 50.124 255.960 50.148 ;
      RECT 0.054 50.220 255.960 50.244 ;
      RECT 0.054 50.316 255.960 50.340 ;
      RECT 0.054 50.412 255.960 50.436 ;
      RECT 0.054 50.508 255.960 50.532 ;
      RECT 0.054 50.604 255.960 50.628 ;
      RECT 0.054 50.700 255.960 50.724 ;
      RECT 0.054 50.796 255.960 50.820 ;
      RECT 0.054 50.892 255.960 50.916 ;
      RECT 0.054 50.988 255.960 51.012 ;
      RECT 0.054 51.084 255.960 51.108 ;
      RECT 0.054 51.180 255.960 51.204 ;
      RECT 0.054 51.276 255.960 51.300 ;
      RECT 0.054 51.372 255.960 51.396 ;
      RECT 0.054 51.468 255.960 51.492 ;
      RECT 0.054 51.564 255.960 51.588 ;
      RECT 0.054 51.660 255.960 51.684 ;
      RECT 0.054 51.756 255.960 51.780 ;
      RECT 0.054 51.852 255.960 51.876 ;
      RECT 0.054 51.948 255.960 51.972 ;
      RECT 0.054 52.044 255.960 52.068 ;
      RECT 0.054 52.140 255.960 52.164 ;
      RECT 0.054 52.236 255.960 52.260 ;
      RECT 0.054 52.332 255.960 52.356 ;
      RECT 0.054 52.428 255.960 52.452 ;
      RECT 0.054 52.524 255.960 52.548 ;
      RECT 0.054 52.620 255.960 52.644 ;
      RECT 0.054 52.716 255.960 52.740 ;
      RECT 0.054 52.812 255.960 52.836 ;
      RECT 0.054 52.908 255.960 52.932 ;
      RECT 0.054 53.004 255.960 53.028 ;
      RECT 0.054 53.100 255.960 53.124 ;
      RECT 0.054 53.196 255.960 53.220 ;
      RECT 0.054 53.292 255.960 53.316 ;
      RECT 0.054 53.388 255.960 53.412 ;
      RECT 0.054 53.484 255.960 53.508 ;
      RECT 0.054 53.580 255.960 53.604 ;
      RECT 0.054 53.676 255.960 53.700 ;
      RECT 0.054 53.772 255.960 53.796 ;
      RECT 0.054 53.868 255.960 53.892 ;
      RECT 0.054 53.964 255.960 53.988 ;
      RECT 0.054 54.060 255.960 54.084 ;
      RECT 0.054 54.156 255.960 54.180 ;
      RECT 0.054 54.252 255.960 54.276 ;
      RECT 0.054 54.348 255.960 54.372 ;
      RECT 0.054 54.444 255.960 54.468 ;
      RECT 0.054 54.540 255.960 54.564 ;
      RECT 0.054 54.636 255.960 54.660 ;
      RECT 0.054 54.732 255.960 54.756 ;
      RECT 0.054 54.828 255.960 54.852 ;
      RECT 0.054 54.924 255.960 54.948 ;
      RECT 0.054 55.020 255.960 55.044 ;
      RECT 0.054 55.116 255.960 55.140 ;
      RECT 0.054 55.212 255.960 55.236 ;
      RECT 0.054 55.308 255.960 55.332 ;
      RECT 0.054 55.404 255.960 55.428 ;
      RECT 0.054 55.500 255.960 55.524 ;
      RECT 0.054 55.596 255.960 55.620 ;
      RECT 0.054 55.692 255.960 55.716 ;
      RECT 0.054 55.788 255.960 55.812 ;
      RECT 0.054 55.884 255.960 55.908 ;
      RECT 0.054 55.980 255.960 56.004 ;
      RECT 0.054 56.076 255.960 56.100 ;
      RECT 0.054 56.172 255.960 56.196 ;
      RECT 0.054 56.268 255.960 56.292 ;
      RECT 0.054 56.364 255.960 56.388 ;
      RECT 0.054 56.460 255.960 56.484 ;
      RECT 0.054 56.556 255.960 56.580 ;
      RECT 0.054 56.652 255.960 56.676 ;
      RECT 0.054 56.748 255.960 56.772 ;
      RECT 0.054 56.844 255.960 56.868 ;
      RECT 0.054 56.940 255.960 56.964 ;
      RECT 0.054 57.036 255.960 57.060 ;
      RECT 0.054 57.132 255.960 57.156 ;
      RECT 0.054 57.228 255.960 57.252 ;
      RECT 0.054 57.324 255.960 57.348 ;
      RECT 0.054 57.420 255.960 57.444 ;
      RECT 0.054 57.516 255.960 57.540 ;
      RECT 0.054 57.612 255.960 57.636 ;
      RECT 0.054 57.708 255.960 57.732 ;
      RECT 0.054 57.804 255.960 57.828 ;
      RECT 0.054 57.900 255.960 57.924 ;
      RECT 0.054 57.996 255.960 58.020 ;
      RECT 0.054 58.092 255.960 58.116 ;
      RECT 0.054 58.188 255.960 58.212 ;
      RECT 0.054 58.284 255.960 58.308 ;
      RECT 0.054 58.380 255.960 58.404 ;
      RECT 0.054 58.476 255.960 58.500 ;
      RECT 0.054 58.572 255.960 58.596 ;
      RECT 0.054 58.668 255.960 58.692 ;
      RECT 0.054 58.764 255.960 58.788 ;
      RECT 0.054 58.860 255.960 58.884 ;
      RECT 0.054 58.956 255.960 58.980 ;
      RECT 0.054 59.052 255.960 59.076 ;
      RECT 0.054 59.148 255.960 59.172 ;
      RECT 0.054 59.244 255.960 59.268 ;
      RECT 0.054 59.340 255.960 59.364 ;
      RECT 0.054 59.436 255.960 59.460 ;
      RECT 0.054 59.532 255.960 59.556 ;
      RECT 0.054 59.628 255.960 59.652 ;
      RECT 0.054 59.724 255.960 59.748 ;
      RECT 0.054 59.820 255.960 59.844 ;
      RECT 0.054 59.916 255.960 59.940 ;
      RECT 0.054 60.012 255.960 60.036 ;
      RECT 0.054 60.108 255.960 60.132 ;
      RECT 0.054 60.204 255.960 60.228 ;
      RECT 0.054 60.300 255.960 60.324 ;
      RECT 0.054 60.396 255.960 60.420 ;
      RECT 0.054 60.492 255.960 60.516 ;
      RECT 0.054 60.588 255.960 60.612 ;
      RECT 0.054 60.684 255.960 60.708 ;
      RECT 0.054 60.780 255.960 60.804 ;
      RECT 0.054 60.876 255.960 60.900 ;
      RECT 0.054 60.972 255.960 60.996 ;
      RECT 0.054 61.068 255.960 61.092 ;
      RECT 0.054 61.164 255.960 61.188 ;
      RECT 0.054 61.260 255.960 61.284 ;
      RECT 0.054 61.356 255.960 61.380 ;
      RECT 0.054 61.452 255.960 61.476 ;
      RECT 0.054 61.548 255.960 61.572 ;
      RECT 0.054 61.644 255.960 61.668 ;
      RECT 0.054 61.740 255.960 61.764 ;
      RECT 0.054 61.836 255.960 61.860 ;
      RECT 0.054 61.932 255.960 61.956 ;
      RECT 0.054 62.028 255.960 62.052 ;
      RECT 0.054 62.124 255.960 62.148 ;
      RECT 0.054 62.220 255.960 62.244 ;
      RECT 0.054 62.316 255.960 62.340 ;
      RECT 0.054 62.412 255.960 62.436 ;
      RECT 0.054 62.508 255.960 62.532 ;
      RECT 0.054 62.604 255.960 62.628 ;
      RECT 0.054 62.700 255.960 62.724 ;
      RECT 0.054 62.796 255.960 62.820 ;
      RECT 0.054 62.892 255.960 62.916 ;
      RECT 0.054 62.988 255.960 63.012 ;
      RECT 0.054 63.084 255.960 63.108 ;
      RECT 0.054 63.180 255.960 63.204 ;
      RECT 0.054 63.276 255.960 63.300 ;
      RECT 0.054 63.372 255.960 63.396 ;
      RECT 0.054 63.468 255.960 63.492 ;
      RECT 0.054 63.564 255.960 63.588 ;
      RECT 0.054 63.660 255.960 63.684 ;
      RECT 0.054 63.756 255.960 63.780 ;
      RECT 0.054 63.852 255.960 63.876 ;
      RECT 0.054 63.948 255.960 63.972 ;
      RECT 0.054 64.044 255.960 64.068 ;
      RECT 0.054 64.140 255.960 64.164 ;
      RECT 0.054 64.236 255.960 64.260 ;
      RECT 0.054 64.332 255.960 64.356 ;
      RECT 0.054 64.428 255.960 64.452 ;
      RECT 0.054 64.524 255.960 64.548 ;
      RECT 0.054 64.620 255.960 64.644 ;
      RECT 0.054 64.716 255.960 64.740 ;
      RECT 0.054 64.812 255.960 64.836 ;
      RECT 0.054 64.908 255.960 64.932 ;
      RECT 0.054 65.004 255.960 65.028 ;
      RECT 0.054 65.100 255.960 65.124 ;
      RECT 0.054 65.196 255.960 65.220 ;
      RECT 0.054 65.292 255.960 65.316 ;
      RECT 0.054 65.388 255.960 65.412 ;
      RECT 0.054 65.484 255.960 65.508 ;
      RECT 0.054 65.580 255.960 65.604 ;
      RECT 0.054 65.676 255.960 65.700 ;
      RECT 0.054 65.772 255.960 65.796 ;
      RECT 0.054 65.868 255.960 65.892 ;
      RECT 0.054 65.964 255.960 65.988 ;
      RECT 0.054 66.060 255.960 66.084 ;
      RECT 0.054 66.156 255.960 66.180 ;
      RECT 0.054 66.252 255.960 66.276 ;
      RECT 0.054 66.348 255.960 66.372 ;
      RECT 0.054 66.444 255.960 66.468 ;
      RECT 0.054 66.540 255.960 66.564 ;
      RECT 0.054 66.636 255.960 66.660 ;
      RECT 0.054 66.732 255.960 66.756 ;
      RECT 0.054 66.828 255.960 66.852 ;
      RECT 0.054 66.924 255.960 66.948 ;
      RECT 0.054 67.020 255.960 67.044 ;
      RECT 0.054 67.116 255.960 67.140 ;
      RECT 0.054 67.212 255.960 67.236 ;
      RECT 0.054 67.308 255.960 67.332 ;
      RECT 0.054 67.404 255.960 67.428 ;
      RECT 0.054 67.500 255.960 67.524 ;
      RECT 0.054 67.596 255.960 67.620 ;
      RECT 0.054 67.692 255.960 67.716 ;
      RECT 0.054 67.788 255.960 67.812 ;
      RECT 0.054 67.884 255.960 67.908 ;
      RECT 0.054 67.980 255.960 68.004 ;
      RECT 0.054 68.076 255.960 68.100 ;
      RECT 0.054 68.172 255.960 68.196 ;
      RECT 0.054 68.268 255.960 68.292 ;
      RECT 0.054 68.364 255.960 68.388 ;
      RECT 0.054 68.460 255.960 68.484 ;
      RECT 0.054 68.556 255.960 68.580 ;
      RECT 0.054 68.652 255.960 68.676 ;
      RECT 0.054 68.748 255.960 68.772 ;
      RECT 0.054 68.844 255.960 68.868 ;
      RECT 0.054 68.940 255.960 68.964 ;
      RECT 0.054 69.036 255.960 69.060 ;
      RECT 0.054 69.132 255.960 69.156 ;
      RECT 0.054 69.228 255.960 69.252 ;
      RECT 0.054 69.324 255.960 69.348 ;
      RECT 0.054 69.420 255.960 69.444 ;
      RECT 0.054 69.516 255.960 69.540 ;
      RECT 0.054 69.612 255.960 69.636 ;
      RECT 0.054 69.708 255.960 69.732 ;
      RECT 0.054 69.804 255.960 69.828 ;
      RECT 0.054 69.900 255.960 69.924 ;
      RECT 0.054 69.996 255.960 70.020 ;
      RECT 0.054 70.092 255.960 70.116 ;
      RECT 0.054 70.188 255.960 70.212 ;
      RECT 0.054 70.284 255.960 70.308 ;
      RECT 0.054 70.380 255.960 70.404 ;
      RECT 0.054 70.476 255.960 70.500 ;
      RECT 0.054 70.572 255.960 70.596 ;
      RECT 0.054 70.668 255.960 70.692 ;
      RECT 0.054 70.764 255.960 70.788 ;
      RECT 0.054 70.860 255.960 70.884 ;
      RECT 0.054 70.956 255.960 70.980 ;
      RECT 0.054 71.052 255.960 71.076 ;
      RECT 0.054 71.148 255.960 71.172 ;
      RECT 0.054 71.244 255.960 71.268 ;
      RECT 0.054 71.340 255.960 71.364 ;
      RECT 0.054 71.436 255.960 71.460 ;
      RECT 0.054 71.532 255.960 71.556 ;
      RECT 0.054 71.628 255.960 71.652 ;
      RECT 0.054 71.724 255.960 71.748 ;
      RECT 0.054 71.820 255.960 71.844 ;
      RECT 0.054 71.916 255.960 71.940 ;
      RECT 0.054 72.012 255.960 72.036 ;
      RECT 0.054 72.108 255.960 72.132 ;
      RECT 0.054 72.204 255.960 72.228 ;
      RECT 0.054 72.300 255.960 72.324 ;
      RECT 0.054 72.396 255.960 72.420 ;
      RECT 0.054 72.492 255.960 72.516 ;
      RECT 0.054 72.588 255.960 72.612 ;
      RECT 0.054 72.684 255.960 72.708 ;
      RECT 0.054 72.780 255.960 72.804 ;
      RECT 0.054 72.876 255.960 72.900 ;
      RECT 0.054 72.972 255.960 72.996 ;
      RECT 0.054 73.068 255.960 73.092 ;
      RECT 0.054 73.164 255.960 73.188 ;
      RECT 0.054 73.260 255.960 73.284 ;
      RECT 0.054 73.356 255.960 73.380 ;
      RECT 0.054 73.452 255.960 73.476 ;
      RECT 0.054 73.548 255.960 73.572 ;
      RECT 0.054 73.644 255.960 73.668 ;
      RECT 0.054 73.740 255.960 73.764 ;
      RECT 0.054 73.836 255.960 73.860 ;
      RECT 0.054 73.932 255.960 73.956 ;
      RECT 0.054 74.028 255.960 74.052 ;
      RECT 0.054 74.124 255.960 74.148 ;
      RECT 0.054 74.220 255.960 74.244 ;
      RECT 0.054 74.316 255.960 74.340 ;
      RECT 0.054 74.412 255.960 74.436 ;
      RECT 0.054 74.508 255.960 74.532 ;
      RECT 0.054 74.604 255.960 74.628 ;
      RECT 0.054 74.700 255.960 74.724 ;
      RECT 0.054 74.796 255.960 74.820 ;
      RECT 0.054 74.892 255.960 74.916 ;
      RECT 0.054 74.988 255.960 75.012 ;
      RECT 0.054 75.084 255.960 75.108 ;
      RECT 0.054 75.180 255.960 75.204 ;
      RECT 0.054 75.276 255.960 75.300 ;
      RECT 0.054 75.372 255.960 75.396 ;
      RECT 0.054 75.468 255.960 75.492 ;
      RECT 0.054 75.564 255.960 75.588 ;
      RECT 0.054 75.660 255.960 75.684 ;
      RECT 0.054 75.756 255.960 75.780 ;
      RECT 0.054 75.852 255.960 75.876 ;
      RECT 0.054 75.948 255.960 75.972 ;
      RECT 0.054 76.044 255.960 76.068 ;
      RECT 0.054 76.140 255.960 76.164 ;
      RECT 0.054 76.236 255.960 76.260 ;
      RECT 0.054 76.332 255.960 76.356 ;
      RECT 0.054 76.428 255.960 76.452 ;
      RECT 0.054 76.524 255.960 76.548 ;
      RECT 0.054 76.620 255.960 76.644 ;
      RECT 0.054 76.716 255.960 76.740 ;
      RECT 0.054 76.812 255.960 76.836 ;
      RECT 0.054 76.908 255.960 76.932 ;
      RECT 0.054 77.004 255.960 77.028 ;
      RECT 0.054 77.100 255.960 77.124 ;
      RECT 0.054 77.196 255.960 77.220 ;
      RECT 0.054 77.292 255.960 77.316 ;
      RECT 0.054 77.388 255.960 77.412 ;
      RECT 0.054 77.484 255.960 77.508 ;
      RECT 0.054 77.580 255.960 77.604 ;
      RECT 0.054 77.676 255.960 77.700 ;
      RECT 0.054 77.772 255.960 77.796 ;
      RECT 0.054 77.868 255.960 77.892 ;
      RECT 0.054 77.964 255.960 77.988 ;
      RECT 0.054 78.060 255.960 78.084 ;
      RECT 0.054 78.156 255.960 78.180 ;
      RECT 0.054 78.252 255.960 78.276 ;
      RECT 0.054 78.348 255.960 78.372 ;
      RECT 0.054 78.444 255.960 78.468 ;
      RECT 0.054 78.540 255.960 78.564 ;
      RECT 0.054 78.636 255.960 78.660 ;
      RECT 0.054 78.732 255.960 78.756 ;
      RECT 0.054 78.828 255.960 78.852 ;
      RECT 0.054 78.924 255.960 78.948 ;
      RECT 0.054 79.020 255.960 79.044 ;
      RECT 0.054 79.116 255.960 79.140 ;
      RECT 0.054 79.212 255.960 79.236 ;
      RECT 0.054 79.308 255.960 79.332 ;
      RECT 0.054 79.404 255.960 79.428 ;
      RECT 0.054 79.500 255.960 79.524 ;
      RECT 0.054 79.596 255.960 79.620 ;
      RECT 0.054 79.692 255.960 79.716 ;
      RECT 0.054 79.788 255.960 79.812 ;
      RECT 0.054 79.884 255.960 79.908 ;
      RECT 0.054 79.980 255.960 80.004 ;
      RECT 0.054 80.076 255.960 80.100 ;
      RECT 0.054 80.172 255.960 80.196 ;
      RECT 0.054 80.268 255.960 80.292 ;
      RECT 0.054 80.364 255.960 80.388 ;
      RECT 0.054 80.460 255.960 80.484 ;
      RECT 0.054 80.556 255.960 80.580 ;
      RECT 0.054 80.652 255.960 80.676 ;
      RECT 0.054 80.748 255.960 80.772 ;
      RECT 0.054 80.844 255.960 80.868 ;
      RECT 0.054 80.940 255.960 80.964 ;
      RECT 0.054 81.036 255.960 81.060 ;
      RECT 0.054 81.132 255.960 81.156 ;
      RECT 0.054 81.228 255.960 81.252 ;
      RECT 0.054 81.324 255.960 81.348 ;
      RECT 0.054 81.420 255.960 81.444 ;
      RECT 0.054 81.516 255.960 81.540 ;
      RECT 0.054 81.612 255.960 81.636 ;
      RECT 0.054 81.708 255.960 81.732 ;
      RECT 0.054 81.804 255.960 81.828 ;
      RECT 0.054 81.900 255.960 81.924 ;
      RECT 0.054 81.996 255.960 82.020 ;
      RECT 0.054 82.092 255.960 82.116 ;
      RECT 0.054 82.188 255.960 82.212 ;
      RECT 0.054 82.284 255.960 82.308 ;
      RECT 0.054 82.380 255.960 82.404 ;
      RECT 0.054 82.476 255.960 82.500 ;
      RECT 0.054 82.572 255.960 82.596 ;
      RECT 0.054 82.668 255.960 82.692 ;
      RECT 0.054 82.764 255.960 82.788 ;
      RECT 0.054 82.860 255.960 82.884 ;
      RECT 0.054 82.956 255.960 82.980 ;
      RECT 0.054 83.052 255.960 83.076 ;
      RECT 0.054 83.148 255.960 83.172 ;
      RECT 0.054 83.244 255.960 83.268 ;
      RECT 0.054 83.340 255.960 83.364 ;
      RECT 0.054 83.436 255.960 83.460 ;
      RECT 0.054 83.532 255.960 83.556 ;
      RECT 0.054 83.628 255.960 83.652 ;
      RECT 0.054 83.724 255.960 83.748 ;
      RECT 0.054 83.820 255.960 83.844 ;
      RECT 0.054 83.916 255.960 83.940 ;
      RECT 0.054 84.012 255.960 84.036 ;
      RECT 0.054 84.108 255.960 84.132 ;
      RECT 0.054 84.204 255.960 84.228 ;
      RECT 0.054 84.300 255.960 84.324 ;
      RECT 0.054 84.396 255.960 84.420 ;
      RECT 0.054 84.492 255.960 84.516 ;
      RECT 0.054 84.588 255.960 84.612 ;
      RECT 0.054 84.684 255.960 84.708 ;
      RECT 0.054 84.780 255.960 84.804 ;
      RECT 0.054 84.876 255.960 84.900 ;
      RECT 0.054 84.972 255.960 84.996 ;
      RECT 0.054 85.068 255.960 85.092 ;
      RECT 0.054 85.164 255.960 85.188 ;
      RECT 0.054 85.260 255.960 85.284 ;
      RECT 0.054 85.356 255.960 85.380 ;
      RECT 0.054 85.452 255.960 85.476 ;
      RECT 0.054 85.548 255.960 85.572 ;
      RECT 0.054 85.644 255.960 85.668 ;
      RECT 0.054 85.740 255.960 85.764 ;
      RECT 0.054 85.836 255.960 85.860 ;
      RECT 0.054 85.932 255.960 85.956 ;
      RECT 0.054 86.028 255.960 86.052 ;
      RECT 0.054 86.124 255.960 86.148 ;
      RECT 0.054 86.220 255.960 86.244 ;
      RECT 0.054 86.316 255.960 86.340 ;
      RECT 0.054 86.412 255.960 86.436 ;
      RECT 0.054 86.508 255.960 86.532 ;
      RECT 0.054 86.604 255.960 86.628 ;
      RECT 0.054 86.700 255.960 86.724 ;
      RECT 0.054 86.796 255.960 86.820 ;
      RECT 0.054 86.892 255.960 86.916 ;
      RECT 0.054 86.988 255.960 87.012 ;
      RECT 0.054 87.084 255.960 87.108 ;
      RECT 0.054 87.180 255.960 87.204 ;
      RECT 0.054 87.276 255.960 87.300 ;
      RECT 0.054 87.372 255.960 87.396 ;
      RECT 0.054 87.468 255.960 87.492 ;
      RECT 0.054 87.564 255.960 87.588 ;
      RECT 0.054 87.660 255.960 87.684 ;
      RECT 0.054 87.756 255.960 87.780 ;
      RECT 0.054 87.852 255.960 87.876 ;
      RECT 0.054 87.948 255.960 87.972 ;
      RECT 0.054 88.044 255.960 88.068 ;
      RECT 0.054 88.140 255.960 88.164 ;
      RECT 0.054 88.236 255.960 88.260 ;
      RECT 0.054 88.332 255.960 88.356 ;
      RECT 0.054 88.428 255.960 88.452 ;
      RECT 0.054 88.524 255.960 88.548 ;
      RECT 0.054 88.620 255.960 88.644 ;
      RECT 0.054 88.716 255.960 88.740 ;
      RECT 0.054 88.812 255.960 88.836 ;
      RECT 0.054 88.908 255.960 88.932 ;
      RECT 0.054 89.004 255.960 89.028 ;
      RECT 0.054 89.100 255.960 89.124 ;
      RECT 0.054 89.196 255.960 89.220 ;
      RECT 0.054 89.292 255.960 89.316 ;
      RECT 0.054 89.388 255.960 89.412 ;
      RECT 0.054 89.484 255.960 89.508 ;
      RECT 0.054 89.580 255.960 89.604 ;
      RECT 0.054 89.676 255.960 89.700 ;
      RECT 0.054 89.772 255.960 89.796 ;
      RECT 0.054 89.868 255.960 89.892 ;
      RECT 0.054 89.964 255.960 89.988 ;
      RECT 0.054 90.060 255.960 90.084 ;
      RECT 0.054 90.156 255.960 90.180 ;
      RECT 0.054 90.252 255.960 90.276 ;
      RECT 0.054 90.348 255.960 90.372 ;
      RECT 0.054 90.444 255.960 90.468 ;
      RECT 0.054 90.540 255.960 90.564 ;
      RECT 0.054 90.636 255.960 90.660 ;
      RECT 0.054 90.732 255.960 90.756 ;
      RECT 0.054 90.828 255.960 90.852 ;
      RECT 0.054 90.924 255.960 90.948 ;
      RECT 0.054 91.020 255.960 91.044 ;
      RECT 0.054 91.116 255.960 91.140 ;
      RECT 0.054 91.212 255.960 91.236 ;
      RECT 0.054 91.308 255.960 91.332 ;
      RECT 0.054 91.404 255.960 91.428 ;
      RECT 0.054 91.500 255.960 91.524 ;
      RECT 0.054 91.596 255.960 91.620 ;
      RECT 0.054 91.692 255.960 91.716 ;
      RECT 0.054 91.788 255.960 91.812 ;
      RECT 0.054 91.884 255.960 91.908 ;
      RECT 0.054 91.980 255.960 92.004 ;
      RECT 0.054 92.076 255.960 92.100 ;
      RECT 0.054 92.172 255.960 92.196 ;
      RECT 0.054 92.268 255.960 92.292 ;
      RECT 0.054 92.364 255.960 92.388 ;
      RECT 0.054 92.460 255.960 92.484 ;
      RECT 0.054 92.556 255.960 92.580 ;
      RECT 0.054 92.652 255.960 92.676 ;
      RECT 0.054 92.748 255.960 92.772 ;
      RECT 0.054 92.844 255.960 92.868 ;
      RECT 0.054 92.940 255.960 92.964 ;
      RECT 0.054 93.036 255.960 93.060 ;
      RECT 0.054 93.132 255.960 93.156 ;
      RECT 0.054 93.228 255.960 93.252 ;
      RECT 0.054 93.324 255.960 93.348 ;
      RECT 0.054 93.420 255.960 93.444 ;
      RECT 0.054 93.516 255.960 93.540 ;
      RECT 0.054 93.612 255.960 93.636 ;
      RECT 0.054 93.708 255.960 93.732 ;
      RECT 0.054 93.804 255.960 93.828 ;
      RECT 0.054 93.900 255.960 93.924 ;
      RECT 0.054 93.996 255.960 94.020 ;
      RECT 0.054 94.092 255.960 94.116 ;
      RECT 0.054 94.188 255.960 94.212 ;
      RECT 0.054 94.284 255.960 94.308 ;
      RECT 0.054 94.380 255.960 94.404 ;
      RECT 0.054 94.476 255.960 94.500 ;
      RECT 0.054 94.572 255.960 94.596 ;
      RECT 0.054 94.668 255.960 94.692 ;
      RECT 0.054 94.764 255.960 94.788 ;
      RECT 0.054 94.860 255.960 94.884 ;
      RECT 0.054 94.956 255.960 94.980 ;
      RECT 0.054 95.052 255.960 95.076 ;
      RECT 0.054 95.148 255.960 95.172 ;
      RECT 0.054 95.244 255.960 95.268 ;
      RECT 0.054 95.340 255.960 95.364 ;
      RECT 0.054 95.436 255.960 95.460 ;
      RECT 0.054 95.532 255.960 95.556 ;
      RECT 0.054 95.628 255.960 95.652 ;
      RECT 0.054 95.724 255.960 95.748 ;
      RECT 0.054 95.820 255.960 95.844 ;
      RECT 0.054 95.916 255.960 95.940 ;
      RECT 0.054 96.012 255.960 96.036 ;
      RECT 0.054 96.108 255.960 96.132 ;
      RECT 0.054 96.204 255.960 96.228 ;
      RECT 0.054 96.300 255.960 96.324 ;
      RECT 0.054 96.396 255.960 96.420 ;
      RECT 0.054 96.492 255.960 96.516 ;
      RECT 0.054 96.588 255.960 96.612 ;
      RECT 0.054 96.684 255.960 96.708 ;
      RECT 0.054 96.780 255.960 96.804 ;
      RECT 0.054 96.876 255.960 96.900 ;
      RECT 0.054 96.972 255.960 96.996 ;
      RECT 0.054 97.068 255.960 97.092 ;
      RECT 0.054 97.164 255.960 97.188 ;
      RECT 0.054 97.260 255.960 97.284 ;
      RECT 0.054 97.356 255.960 97.380 ;
      RECT 0.054 97.452 255.960 97.476 ;
      RECT 0.054 97.548 255.960 97.572 ;
      RECT 0.054 97.644 255.960 97.668 ;
      RECT 0.054 97.740 255.960 97.764 ;
      RECT 0.054 97.836 255.960 97.860 ;
      RECT 0.054 97.932 255.960 97.956 ;
      RECT 0.054 98.028 255.960 98.052 ;
      RECT 0.054 98.124 255.960 98.148 ;
      RECT 0.054 98.220 255.960 98.244 ;
      RECT 0.054 98.316 255.960 98.340 ;
      RECT 0.054 98.412 255.960 98.436 ;
      RECT 0.054 98.508 255.960 98.532 ;
      RECT 0.054 98.604 255.960 98.628 ;
      RECT 0.054 98.700 255.960 98.724 ;
      RECT 0.054 98.796 255.960 98.820 ;
      RECT 0.054 98.892 255.960 98.916 ;
      RECT 0.054 98.988 255.960 99.012 ;
      RECT 0.054 99.084 255.960 99.108 ;
      RECT 0.054 99.180 255.960 99.204 ;
      RECT 0.054 99.276 255.960 99.300 ;
      RECT 0.054 99.372 255.960 99.396 ;
      RECT 0.054 99.468 255.960 99.492 ;
      RECT 0.054 99.564 255.960 99.588 ;
      RECT 0.054 99.660 255.960 99.684 ;
      RECT 0.054 99.756 255.960 99.780 ;
      RECT 0.054 99.852 255.960 99.876 ;
      RECT 0.054 99.948 255.960 99.972 ;
      RECT 0.054 100.044 255.960 100.068 ;
      RECT 0.054 100.140 255.960 100.164 ;
      RECT 0.054 100.236 255.960 100.260 ;
      RECT 0.054 100.332 255.960 100.356 ;
      RECT 0.054 100.428 255.960 100.452 ;
      RECT 0.054 100.524 255.960 100.548 ;
      RECT 0.054 100.620 255.960 100.644 ;
      RECT 0.054 100.716 255.960 100.740 ;
      RECT 0.054 100.812 255.960 100.836 ;
      RECT 0.054 100.908 255.960 100.932 ;
      RECT 0.054 101.004 255.960 101.028 ;
      RECT 0.054 101.100 255.960 101.124 ;
      RECT 0.054 101.196 255.960 101.220 ;
      RECT 0.054 101.292 255.960 101.316 ;
      RECT 0.054 101.388 255.960 101.412 ;
      RECT 0.054 101.484 255.960 101.508 ;
      RECT 0.054 101.580 255.960 101.604 ;
      RECT 0.054 101.676 255.960 101.700 ;
      RECT 0.054 101.772 255.960 101.796 ;
      RECT 0.054 101.868 255.960 101.892 ;
      RECT 0.054 101.964 255.960 101.988 ;
      RECT 0.054 102.060 255.960 102.084 ;
      RECT 0.054 102.156 255.960 102.180 ;
      RECT 0.054 102.252 255.960 102.276 ;
      RECT 0.054 102.348 255.960 102.372 ;
      RECT 0.054 102.444 255.960 102.468 ;
      RECT 0.054 102.540 255.960 102.564 ;
      RECT 0.054 102.636 255.960 102.660 ;
      RECT 0.054 102.732 255.960 102.756 ;
      RECT 0.054 102.828 255.960 102.852 ;
      RECT 0.054 102.924 255.960 102.948 ;
      RECT 0.054 103.020 255.960 103.044 ;
      RECT 0.054 103.116 255.960 103.140 ;
      RECT 0.054 103.212 255.960 103.236 ;
      RECT 0.054 103.308 255.960 103.332 ;
      RECT 0.054 103.404 255.960 103.428 ;
      RECT 0.054 103.500 255.960 103.524 ;
      RECT 0.054 103.596 255.960 103.620 ;
      RECT 0.054 103.692 255.960 103.716 ;
      RECT 0.054 103.788 255.960 103.812 ;
      RECT 0.054 103.884 255.960 103.908 ;
      RECT 0.054 103.980 255.960 104.004 ;
      RECT 0.054 104.076 255.960 104.100 ;
      RECT 0.054 104.172 255.960 104.196 ;
      RECT 0.054 104.268 255.960 104.292 ;
      RECT 0.054 104.364 255.960 104.388 ;
      RECT 0.054 104.460 255.960 104.484 ;
      RECT 0.054 104.556 255.960 104.580 ;
      RECT 0.054 104.652 255.960 104.676 ;
      RECT 0.054 104.748 255.960 104.772 ;
      RECT 0.054 104.844 255.960 104.868 ;
      RECT 0.054 104.940 255.960 104.964 ;
      RECT 0.054 105.036 255.960 105.060 ;
      RECT 0.054 105.132 255.960 105.156 ;
      RECT 0.054 105.228 255.960 105.252 ;
      RECT 0.054 105.324 255.960 105.348 ;
      RECT 0.054 105.420 255.960 105.444 ;
      RECT 0.054 105.516 255.960 105.540 ;
      RECT 0.054 105.612 255.960 105.636 ;
      RECT 0.054 105.708 255.960 105.732 ;
      RECT 0.054 105.804 255.960 105.828 ;
      RECT 0.054 105.900 255.960 105.924 ;
      RECT 0.054 105.996 255.960 106.020 ;
      RECT 0.054 106.092 255.960 106.116 ;
      RECT 0.054 106.188 255.960 106.212 ;
      RECT 0.054 106.284 255.960 106.308 ;
      RECT 0.054 106.380 255.960 106.404 ;
      RECT 0.054 106.476 255.960 106.500 ;
      RECT 0.054 106.572 255.960 106.596 ;
      RECT 0.054 106.668 255.960 106.692 ;
      RECT 0.054 106.764 255.960 106.788 ;
      RECT 0.054 106.860 255.960 106.884 ;
      RECT 0.054 106.956 255.960 106.980 ;
      RECT 0.054 107.052 255.960 107.076 ;
      RECT 0.054 107.148 255.960 107.172 ;
      RECT 0.054 107.244 255.960 107.268 ;
      RECT 0.054 107.340 255.960 107.364 ;
      RECT 0.054 107.436 255.960 107.460 ;
      RECT 0.054 107.532 255.960 107.556 ;
      RECT 0.054 107.628 255.960 107.652 ;
      RECT 0.054 107.724 255.960 107.748 ;
      RECT 0.054 107.820 255.960 107.844 ;
      RECT 0.054 107.916 255.960 107.940 ;
      RECT 0.054 108.012 255.960 108.036 ;
      RECT 0.054 108.108 255.960 108.132 ;
      RECT 0.054 108.204 255.960 108.228 ;
      RECT 0.054 108.300 255.960 108.324 ;
      RECT 0.054 108.396 255.960 108.420 ;
      RECT 0.054 108.492 255.960 108.516 ;
      RECT 0.054 108.588 255.960 108.612 ;
      RECT 0.054 108.684 255.960 108.708 ;
      RECT 0.054 108.780 255.960 108.804 ;
      RECT 0.054 108.876 255.960 108.900 ;
      RECT 0.054 108.972 255.960 108.996 ;
      RECT 0.054 109.068 255.960 109.092 ;
      RECT 0.054 109.164 255.960 109.188 ;
      RECT 0.054 109.260 255.960 109.284 ;
      RECT 0.054 109.356 255.960 109.380 ;
      RECT 0.054 109.452 255.960 109.476 ;
      RECT 0.054 109.548 255.960 109.572 ;
      RECT 0.054 109.644 255.960 109.668 ;
      RECT 0.054 109.740 255.960 109.764 ;
      RECT 0.054 109.836 255.960 109.860 ;
      RECT 0.054 109.932 255.960 109.956 ;
      RECT 0.054 110.028 255.960 110.052 ;
      RECT 0.054 110.124 255.960 110.148 ;
      RECT 0.054 110.220 255.960 110.244 ;
      RECT 0.054 110.316 255.960 110.340 ;
      RECT 0.054 110.412 255.960 110.436 ;
      RECT 0.054 110.508 255.960 110.532 ;
      RECT 0.054 110.604 255.960 110.628 ;
      RECT 0.054 110.700 255.960 110.724 ;
      RECT 0.054 110.796 255.960 110.820 ;
      RECT 0.054 110.892 255.960 110.916 ;
      RECT 0.054 110.988 255.960 111.012 ;
      RECT 0.054 111.084 255.960 111.108 ;
      RECT 0.054 111.180 255.960 111.204 ;
      RECT 0.054 111.276 255.960 111.300 ;
      RECT 0.054 111.372 255.960 111.396 ;
      RECT 0.054 111.468 255.960 111.492 ;
      RECT 0.054 111.564 255.960 111.588 ;
      RECT 0.054 111.660 255.960 111.684 ;
      RECT 0.054 111.756 255.960 111.780 ;
      RECT 0.054 111.852 255.960 111.876 ;
      RECT 0.054 111.948 255.960 111.972 ;
      RECT 0.054 112.044 255.960 112.068 ;
      RECT 0.054 112.140 255.960 112.164 ;
      RECT 0.054 112.236 255.960 112.260 ;
      RECT 0.054 112.332 255.960 112.356 ;
      RECT 0.054 112.428 255.960 112.452 ;
      RECT 0.054 112.524 255.960 112.548 ;
      RECT 0.054 112.620 255.960 112.644 ;
      RECT 0.054 112.716 255.960 112.740 ;
      RECT 0.054 112.812 255.960 112.836 ;
      RECT 0.054 112.908 255.960 112.932 ;
      RECT 0.054 113.004 255.960 113.028 ;
      RECT 0.054 113.100 255.960 113.124 ;
      RECT 0.054 113.196 255.960 113.220 ;
      RECT 0.054 113.292 255.960 113.316 ;
      RECT 0.054 113.388 255.960 113.412 ;
      RECT 0.054 113.484 255.960 113.508 ;
      RECT 0.054 113.580 255.960 113.604 ;
      RECT 0.054 113.676 255.960 113.700 ;
      RECT 0.054 113.772 255.960 113.796 ;
      RECT 0.054 113.868 255.960 113.892 ;
      RECT 0.054 113.964 255.960 113.988 ;
      RECT 0.054 114.060 255.960 114.084 ;
      RECT 0.054 114.156 255.960 114.180 ;
      RECT 0.054 114.252 255.960 114.276 ;
      RECT 0.054 114.348 255.960 114.372 ;
      RECT 0.054 114.444 255.960 114.468 ;
      RECT 0.054 114.540 255.960 114.564 ;
      RECT 0.054 114.636 255.960 114.660 ;
      RECT 0.054 114.732 255.960 114.756 ;
      RECT 0.054 114.828 255.960 114.852 ;
      RECT 0.054 114.924 255.960 114.948 ;
      RECT 0.054 115.020 255.960 115.044 ;
      RECT 0.054 115.116 255.960 115.140 ;
      RECT 0.054 115.212 255.960 115.236 ;
      RECT 0.054 115.308 255.960 115.332 ;
      RECT 0.054 115.404 255.960 115.428 ;
      RECT 0.054 115.500 255.960 115.524 ;
      RECT 0.054 115.596 255.960 115.620 ;
      RECT 0.054 115.692 255.960 115.716 ;
      RECT 0.054 115.788 255.960 115.812 ;
      RECT 0.054 115.884 255.960 115.908 ;
      RECT 0.054 115.980 255.960 116.004 ;
      RECT 0.054 116.076 255.960 116.100 ;
      RECT 0.054 116.172 255.960 116.196 ;
      RECT 0.054 116.268 255.960 116.292 ;
      RECT 0.054 116.364 255.960 116.388 ;
      RECT 0.054 116.460 255.960 116.484 ;
      RECT 0.054 116.556 255.960 116.580 ;
      RECT 0.054 116.652 255.960 116.676 ;
      RECT 0.054 116.748 255.960 116.772 ;
      RECT 0.054 116.844 255.960 116.868 ;
      RECT 0.054 116.940 255.960 116.964 ;
      RECT 0.054 117.036 255.960 117.060 ;
      RECT 0.054 117.132 255.960 117.156 ;
      RECT 0.054 117.228 255.960 117.252 ;
      RECT 0.054 117.324 255.960 117.348 ;
      RECT 0.054 117.420 255.960 117.444 ;
      RECT 0.054 117.516 255.960 117.540 ;
      RECT 0.054 117.612 255.960 117.636 ;
      RECT 0.054 117.708 255.960 117.732 ;
      RECT 0.054 117.804 255.960 117.828 ;
      RECT 0.054 117.900 255.960 117.924 ;
      RECT 0.054 117.996 255.960 118.020 ;
      RECT 0.054 118.092 255.960 118.116 ;
      RECT 0.054 118.188 255.960 118.212 ;
      RECT 0.054 118.284 255.960 118.308 ;
      RECT 0.054 118.380 255.960 118.404 ;
      RECT 0.054 118.476 255.960 118.500 ;
      RECT 0.054 118.572 255.960 118.596 ;
      RECT 0.054 118.668 255.960 118.692 ;
      RECT 0.054 118.764 255.960 118.788 ;
      RECT 0.054 118.860 255.960 118.884 ;
      RECT 0.054 118.956 255.960 118.980 ;
      RECT 0.054 119.052 255.960 119.076 ;
      RECT 0.054 119.148 255.960 119.172 ;
      RECT 0.054 119.244 255.960 119.268 ;
      RECT 0.054 119.340 255.960 119.364 ;
      RECT 0.054 119.436 255.960 119.460 ;
      RECT 0.054 119.532 255.960 119.556 ;
      RECT 0.054 119.628 255.960 119.652 ;
      RECT 0.054 119.724 255.960 119.748 ;
      RECT 0.054 119.820 255.960 119.844 ;
      RECT 0.054 119.916 255.960 119.940 ;
      RECT 0.054 120.012 255.960 120.036 ;
      RECT 0.054 120.108 255.960 120.132 ;
      RECT 0.054 120.204 255.960 120.228 ;
      RECT 0.054 120.300 255.960 120.324 ;
      RECT 0.054 120.396 255.960 120.420 ;
      RECT 0.054 120.492 255.960 120.516 ;
      RECT 0.054 120.588 255.960 120.612 ;
      RECT 0.054 120.684 255.960 120.708 ;
      RECT 0.054 120.780 255.960 120.804 ;
      RECT 0.054 120.876 255.960 120.900 ;
      RECT 0.054 120.972 255.960 120.996 ;
      RECT 0.054 121.068 255.960 121.092 ;
      RECT 0.054 121.164 255.960 121.188 ;
      RECT 0.054 121.260 255.960 121.284 ;
      RECT 0.054 121.356 255.960 121.380 ;
      RECT 0.054 121.452 255.960 121.476 ;
      RECT 0.054 121.548 255.960 121.572 ;
      RECT 0.054 121.644 255.960 121.668 ;
      RECT 0.054 121.740 255.960 121.764 ;
      RECT 0.054 121.836 255.960 121.860 ;
      RECT 0.054 121.932 255.960 121.956 ;
      RECT 0.054 122.028 255.960 122.052 ;
      RECT 0.054 122.124 255.960 122.148 ;
      RECT 0.054 122.220 255.960 122.244 ;
      RECT 0.054 122.316 255.960 122.340 ;
      RECT 0.054 122.412 255.960 122.436 ;
      RECT 0.054 122.508 255.960 122.532 ;
      RECT 0.054 122.604 255.960 122.628 ;
      RECT 0.054 122.700 255.960 122.724 ;
      RECT 0.054 122.796 255.960 122.820 ;
      RECT 0.054 122.892 255.960 122.916 ;
      RECT 0.054 122.988 255.960 123.012 ;
      RECT 0.054 123.084 255.960 123.108 ;
      RECT 0.054 123.180 255.960 123.204 ;
      RECT 0.054 123.276 255.960 123.300 ;
      RECT 0.054 123.372 255.960 123.396 ;
      RECT 0.054 123.468 255.960 123.492 ;
      RECT 0.054 123.564 255.960 123.588 ;
      RECT 0.054 123.660 255.960 123.684 ;
      RECT 0.054 123.756 255.960 123.780 ;
      RECT 0.054 123.852 255.960 123.876 ;
      RECT 0.054 123.948 255.960 123.972 ;
      RECT 0.054 124.044 255.960 124.068 ;
      RECT 0.054 124.140 255.960 124.164 ;
      RECT 0.054 124.236 255.960 124.260 ;
      RECT 0.054 124.332 255.960 124.356 ;
      RECT 0.054 124.428 255.960 124.452 ;
      RECT 0.054 124.524 255.960 124.548 ;
      RECT 0.054 124.620 255.960 124.644 ;
      RECT 0.054 124.716 255.960 124.740 ;
      RECT 0.054 124.812 255.960 124.836 ;
      RECT 0.054 124.908 255.960 124.932 ;
      RECT 0.054 125.004 255.960 125.028 ;
      RECT 0.054 125.100 255.960 125.124 ;
      RECT 0.054 125.196 255.960 125.220 ;
      RECT 0.054 125.292 255.960 125.316 ;
      RECT 0.054 125.388 255.960 125.412 ;
      RECT 0.054 125.484 255.960 125.508 ;
      RECT 0.054 125.580 255.960 125.604 ;
      RECT 0.054 125.676 255.960 125.700 ;
      RECT 0.054 125.772 255.960 125.796 ;
      RECT 0.054 125.868 255.960 125.892 ;
      RECT 0.054 125.964 255.960 125.988 ;
      RECT 0.054 126.060 255.960 126.084 ;
      RECT 0.054 126.156 255.960 126.180 ;
      RECT 0.054 126.252 255.960 126.276 ;
      RECT 0.054 126.348 255.960 126.372 ;
      RECT 0.054 126.444 255.960 126.468 ;
      RECT 0.054 126.540 255.960 126.564 ;
      RECT 0.054 126.636 255.960 126.660 ;
      RECT 0.054 126.732 255.960 126.756 ;
      RECT 0.054 126.828 255.960 126.852 ;
      RECT 0.054 126.924 255.960 126.948 ;
      RECT 0.054 127.020 255.960 127.044 ;
      RECT 0.054 127.116 255.960 127.140 ;
      RECT 0.054 127.212 255.960 127.236 ;
      RECT 0.054 127.308 255.960 127.332 ;
      RECT 0.054 127.404 255.960 127.428 ;
      RECT 0.054 127.500 255.960 127.524 ;
      RECT 0.054 127.596 255.960 127.620 ;
      RECT 0.054 127.692 255.960 127.716 ;
      RECT 0.054 127.788 255.960 127.812 ;
      RECT 0.054 127.884 255.960 127.908 ;
      RECT 0.054 127.980 255.960 128.004 ;
      RECT 0.054 128.076 255.960 128.100 ;
      RECT 0.054 128.172 255.960 128.196 ;
    END
  END VDD
  PIN VSS
    DIRECTION INOUT ;
    USE GROUND ;
    PORT
      LAYER M4 ;
      RECT 0.054 0.060 255.960 0.084 ;
      RECT 0.054 0.156 255.960 0.180 ;
      RECT 0.054 0.252 255.960 0.276 ;
      RECT 0.054 0.348 255.960 0.372 ;
      RECT 0.054 0.444 255.960 0.468 ;
      RECT 0.054 0.540 255.960 0.564 ;
      RECT 0.054 0.636 255.960 0.660 ;
      RECT 0.054 0.732 255.960 0.756 ;
      RECT 0.054 0.828 255.960 0.852 ;
      RECT 0.054 0.924 255.960 0.948 ;
      RECT 0.054 1.020 255.960 1.044 ;
      RECT 0.054 1.116 255.960 1.140 ;
      RECT 0.054 1.212 255.960 1.236 ;
      RECT 0.054 1.308 255.960 1.332 ;
      RECT 0.054 1.404 255.960 1.428 ;
      RECT 0.054 1.500 255.960 1.524 ;
      RECT 0.054 1.596 255.960 1.620 ;
      RECT 0.054 1.692 255.960 1.716 ;
      RECT 0.054 1.788 255.960 1.812 ;
      RECT 0.054 1.884 255.960 1.908 ;
      RECT 0.054 1.980 255.960 2.004 ;
      RECT 0.054 2.076 255.960 2.100 ;
      RECT 0.054 2.172 255.960 2.196 ;
      RECT 0.054 2.268 255.960 2.292 ;
      RECT 0.054 2.364 255.960 2.388 ;
      RECT 0.054 2.460 255.960 2.484 ;
      RECT 0.054 2.556 255.960 2.580 ;
      RECT 0.054 2.652 255.960 2.676 ;
      RECT 0.054 2.748 255.960 2.772 ;
      RECT 0.054 2.844 255.960 2.868 ;
      RECT 0.054 2.940 255.960 2.964 ;
      RECT 0.054 3.036 255.960 3.060 ;
      RECT 0.054 3.132 255.960 3.156 ;
      RECT 0.054 3.228 255.960 3.252 ;
      RECT 0.054 3.324 255.960 3.348 ;
      RECT 0.054 3.420 255.960 3.444 ;
      RECT 0.054 3.516 255.960 3.540 ;
      RECT 0.054 3.612 255.960 3.636 ;
      RECT 0.054 3.708 255.960 3.732 ;
      RECT 0.054 3.804 255.960 3.828 ;
      RECT 0.054 3.900 255.960 3.924 ;
      RECT 0.054 3.996 255.960 4.020 ;
      RECT 0.054 4.092 255.960 4.116 ;
      RECT 0.054 4.188 255.960 4.212 ;
      RECT 0.054 4.284 255.960 4.308 ;
      RECT 0.054 4.380 255.960 4.404 ;
      RECT 0.054 4.476 255.960 4.500 ;
      RECT 0.054 4.572 255.960 4.596 ;
      RECT 0.054 4.668 255.960 4.692 ;
      RECT 0.054 4.764 255.960 4.788 ;
      RECT 0.054 4.860 255.960 4.884 ;
      RECT 0.054 4.956 255.960 4.980 ;
      RECT 0.054 5.052 255.960 5.076 ;
      RECT 0.054 5.148 255.960 5.172 ;
      RECT 0.054 5.244 255.960 5.268 ;
      RECT 0.054 5.340 255.960 5.364 ;
      RECT 0.054 5.436 255.960 5.460 ;
      RECT 0.054 5.532 255.960 5.556 ;
      RECT 0.054 5.628 255.960 5.652 ;
      RECT 0.054 5.724 255.960 5.748 ;
      RECT 0.054 5.820 255.960 5.844 ;
      RECT 0.054 5.916 255.960 5.940 ;
      RECT 0.054 6.012 255.960 6.036 ;
      RECT 0.054 6.108 255.960 6.132 ;
      RECT 0.054 6.204 255.960 6.228 ;
      RECT 0.054 6.300 255.960 6.324 ;
      RECT 0.054 6.396 255.960 6.420 ;
      RECT 0.054 6.492 255.960 6.516 ;
      RECT 0.054 6.588 255.960 6.612 ;
      RECT 0.054 6.684 255.960 6.708 ;
      RECT 0.054 6.780 255.960 6.804 ;
      RECT 0.054 6.876 255.960 6.900 ;
      RECT 0.054 6.972 255.960 6.996 ;
      RECT 0.054 7.068 255.960 7.092 ;
      RECT 0.054 7.164 255.960 7.188 ;
      RECT 0.054 7.260 255.960 7.284 ;
      RECT 0.054 7.356 255.960 7.380 ;
      RECT 0.054 7.452 255.960 7.476 ;
      RECT 0.054 7.548 255.960 7.572 ;
      RECT 0.054 7.644 255.960 7.668 ;
      RECT 0.054 7.740 255.960 7.764 ;
      RECT 0.054 7.836 255.960 7.860 ;
      RECT 0.054 7.932 255.960 7.956 ;
      RECT 0.054 8.028 255.960 8.052 ;
      RECT 0.054 8.124 255.960 8.148 ;
      RECT 0.054 8.220 255.960 8.244 ;
      RECT 0.054 8.316 255.960 8.340 ;
      RECT 0.054 8.412 255.960 8.436 ;
      RECT 0.054 8.508 255.960 8.532 ;
      RECT 0.054 8.604 255.960 8.628 ;
      RECT 0.054 8.700 255.960 8.724 ;
      RECT 0.054 8.796 255.960 8.820 ;
      RECT 0.054 8.892 255.960 8.916 ;
      RECT 0.054 8.988 255.960 9.012 ;
      RECT 0.054 9.084 255.960 9.108 ;
      RECT 0.054 9.180 255.960 9.204 ;
      RECT 0.054 9.276 255.960 9.300 ;
      RECT 0.054 9.372 255.960 9.396 ;
      RECT 0.054 9.468 255.960 9.492 ;
      RECT 0.054 9.564 255.960 9.588 ;
      RECT 0.054 9.660 255.960 9.684 ;
      RECT 0.054 9.756 255.960 9.780 ;
      RECT 0.054 9.852 255.960 9.876 ;
      RECT 0.054 9.948 255.960 9.972 ;
      RECT 0.054 10.044 255.960 10.068 ;
      RECT 0.054 10.140 255.960 10.164 ;
      RECT 0.054 10.236 255.960 10.260 ;
      RECT 0.054 10.332 255.960 10.356 ;
      RECT 0.054 10.428 255.960 10.452 ;
      RECT 0.054 10.524 255.960 10.548 ;
      RECT 0.054 10.620 255.960 10.644 ;
      RECT 0.054 10.716 255.960 10.740 ;
      RECT 0.054 10.812 255.960 10.836 ;
      RECT 0.054 10.908 255.960 10.932 ;
      RECT 0.054 11.004 255.960 11.028 ;
      RECT 0.054 11.100 255.960 11.124 ;
      RECT 0.054 11.196 255.960 11.220 ;
      RECT 0.054 11.292 255.960 11.316 ;
      RECT 0.054 11.388 255.960 11.412 ;
      RECT 0.054 11.484 255.960 11.508 ;
      RECT 0.054 11.580 255.960 11.604 ;
      RECT 0.054 11.676 255.960 11.700 ;
      RECT 0.054 11.772 255.960 11.796 ;
      RECT 0.054 11.868 255.960 11.892 ;
      RECT 0.054 11.964 255.960 11.988 ;
      RECT 0.054 12.060 255.960 12.084 ;
      RECT 0.054 12.156 255.960 12.180 ;
      RECT 0.054 12.252 255.960 12.276 ;
      RECT 0.054 12.348 255.960 12.372 ;
      RECT 0.054 12.444 255.960 12.468 ;
      RECT 0.054 12.540 255.960 12.564 ;
      RECT 0.054 12.636 255.960 12.660 ;
      RECT 0.054 12.732 255.960 12.756 ;
      RECT 0.054 12.828 255.960 12.852 ;
      RECT 0.054 12.924 255.960 12.948 ;
      RECT 0.054 13.020 255.960 13.044 ;
      RECT 0.054 13.116 255.960 13.140 ;
      RECT 0.054 13.212 255.960 13.236 ;
      RECT 0.054 13.308 255.960 13.332 ;
      RECT 0.054 13.404 255.960 13.428 ;
      RECT 0.054 13.500 255.960 13.524 ;
      RECT 0.054 13.596 255.960 13.620 ;
      RECT 0.054 13.692 255.960 13.716 ;
      RECT 0.054 13.788 255.960 13.812 ;
      RECT 0.054 13.884 255.960 13.908 ;
      RECT 0.054 13.980 255.960 14.004 ;
      RECT 0.054 14.076 255.960 14.100 ;
      RECT 0.054 14.172 255.960 14.196 ;
      RECT 0.054 14.268 255.960 14.292 ;
      RECT 0.054 14.364 255.960 14.388 ;
      RECT 0.054 14.460 255.960 14.484 ;
      RECT 0.054 14.556 255.960 14.580 ;
      RECT 0.054 14.652 255.960 14.676 ;
      RECT 0.054 14.748 255.960 14.772 ;
      RECT 0.054 14.844 255.960 14.868 ;
      RECT 0.054 14.940 255.960 14.964 ;
      RECT 0.054 15.036 255.960 15.060 ;
      RECT 0.054 15.132 255.960 15.156 ;
      RECT 0.054 15.228 255.960 15.252 ;
      RECT 0.054 15.324 255.960 15.348 ;
      RECT 0.054 15.420 255.960 15.444 ;
      RECT 0.054 15.516 255.960 15.540 ;
      RECT 0.054 15.612 255.960 15.636 ;
      RECT 0.054 15.708 255.960 15.732 ;
      RECT 0.054 15.804 255.960 15.828 ;
      RECT 0.054 15.900 255.960 15.924 ;
      RECT 0.054 15.996 255.960 16.020 ;
      RECT 0.054 16.092 255.960 16.116 ;
      RECT 0.054 16.188 255.960 16.212 ;
      RECT 0.054 16.284 255.960 16.308 ;
      RECT 0.054 16.380 255.960 16.404 ;
      RECT 0.054 16.476 255.960 16.500 ;
      RECT 0.054 16.572 255.960 16.596 ;
      RECT 0.054 16.668 255.960 16.692 ;
      RECT 0.054 16.764 255.960 16.788 ;
      RECT 0.054 16.860 255.960 16.884 ;
      RECT 0.054 16.956 255.960 16.980 ;
      RECT 0.054 17.052 255.960 17.076 ;
      RECT 0.054 17.148 255.960 17.172 ;
      RECT 0.054 17.244 255.960 17.268 ;
      RECT 0.054 17.340 255.960 17.364 ;
      RECT 0.054 17.436 255.960 17.460 ;
      RECT 0.054 17.532 255.960 17.556 ;
      RECT 0.054 17.628 255.960 17.652 ;
      RECT 0.054 17.724 255.960 17.748 ;
      RECT 0.054 17.820 255.960 17.844 ;
      RECT 0.054 17.916 255.960 17.940 ;
      RECT 0.054 18.012 255.960 18.036 ;
      RECT 0.054 18.108 255.960 18.132 ;
      RECT 0.054 18.204 255.960 18.228 ;
      RECT 0.054 18.300 255.960 18.324 ;
      RECT 0.054 18.396 255.960 18.420 ;
      RECT 0.054 18.492 255.960 18.516 ;
      RECT 0.054 18.588 255.960 18.612 ;
      RECT 0.054 18.684 255.960 18.708 ;
      RECT 0.054 18.780 255.960 18.804 ;
      RECT 0.054 18.876 255.960 18.900 ;
      RECT 0.054 18.972 255.960 18.996 ;
      RECT 0.054 19.068 255.960 19.092 ;
      RECT 0.054 19.164 255.960 19.188 ;
      RECT 0.054 19.260 255.960 19.284 ;
      RECT 0.054 19.356 255.960 19.380 ;
      RECT 0.054 19.452 255.960 19.476 ;
      RECT 0.054 19.548 255.960 19.572 ;
      RECT 0.054 19.644 255.960 19.668 ;
      RECT 0.054 19.740 255.960 19.764 ;
      RECT 0.054 19.836 255.960 19.860 ;
      RECT 0.054 19.932 255.960 19.956 ;
      RECT 0.054 20.028 255.960 20.052 ;
      RECT 0.054 20.124 255.960 20.148 ;
      RECT 0.054 20.220 255.960 20.244 ;
      RECT 0.054 20.316 255.960 20.340 ;
      RECT 0.054 20.412 255.960 20.436 ;
      RECT 0.054 20.508 255.960 20.532 ;
      RECT 0.054 20.604 255.960 20.628 ;
      RECT 0.054 20.700 255.960 20.724 ;
      RECT 0.054 20.796 255.960 20.820 ;
      RECT 0.054 20.892 255.960 20.916 ;
      RECT 0.054 20.988 255.960 21.012 ;
      RECT 0.054 21.084 255.960 21.108 ;
      RECT 0.054 21.180 255.960 21.204 ;
      RECT 0.054 21.276 255.960 21.300 ;
      RECT 0.054 21.372 255.960 21.396 ;
      RECT 0.054 21.468 255.960 21.492 ;
      RECT 0.054 21.564 255.960 21.588 ;
      RECT 0.054 21.660 255.960 21.684 ;
      RECT 0.054 21.756 255.960 21.780 ;
      RECT 0.054 21.852 255.960 21.876 ;
      RECT 0.054 21.948 255.960 21.972 ;
      RECT 0.054 22.044 255.960 22.068 ;
      RECT 0.054 22.140 255.960 22.164 ;
      RECT 0.054 22.236 255.960 22.260 ;
      RECT 0.054 22.332 255.960 22.356 ;
      RECT 0.054 22.428 255.960 22.452 ;
      RECT 0.054 22.524 255.960 22.548 ;
      RECT 0.054 22.620 255.960 22.644 ;
      RECT 0.054 22.716 255.960 22.740 ;
      RECT 0.054 22.812 255.960 22.836 ;
      RECT 0.054 22.908 255.960 22.932 ;
      RECT 0.054 23.004 255.960 23.028 ;
      RECT 0.054 23.100 255.960 23.124 ;
      RECT 0.054 23.196 255.960 23.220 ;
      RECT 0.054 23.292 255.960 23.316 ;
      RECT 0.054 23.388 255.960 23.412 ;
      RECT 0.054 23.484 255.960 23.508 ;
      RECT 0.054 23.580 255.960 23.604 ;
      RECT 0.054 23.676 255.960 23.700 ;
      RECT 0.054 23.772 255.960 23.796 ;
      RECT 0.054 23.868 255.960 23.892 ;
      RECT 0.054 23.964 255.960 23.988 ;
      RECT 0.054 24.060 255.960 24.084 ;
      RECT 0.054 24.156 255.960 24.180 ;
      RECT 0.054 24.252 255.960 24.276 ;
      RECT 0.054 24.348 255.960 24.372 ;
      RECT 0.054 24.444 255.960 24.468 ;
      RECT 0.054 24.540 255.960 24.564 ;
      RECT 0.054 24.636 255.960 24.660 ;
      RECT 0.054 24.732 255.960 24.756 ;
      RECT 0.054 24.828 255.960 24.852 ;
      RECT 0.054 24.924 255.960 24.948 ;
      RECT 0.054 25.020 255.960 25.044 ;
      RECT 0.054 25.116 255.960 25.140 ;
      RECT 0.054 25.212 255.960 25.236 ;
      RECT 0.054 25.308 255.960 25.332 ;
      RECT 0.054 25.404 255.960 25.428 ;
      RECT 0.054 25.500 255.960 25.524 ;
      RECT 0.054 25.596 255.960 25.620 ;
      RECT 0.054 25.692 255.960 25.716 ;
      RECT 0.054 25.788 255.960 25.812 ;
      RECT 0.054 25.884 255.960 25.908 ;
      RECT 0.054 25.980 255.960 26.004 ;
      RECT 0.054 26.076 255.960 26.100 ;
      RECT 0.054 26.172 255.960 26.196 ;
      RECT 0.054 26.268 255.960 26.292 ;
      RECT 0.054 26.364 255.960 26.388 ;
      RECT 0.054 26.460 255.960 26.484 ;
      RECT 0.054 26.556 255.960 26.580 ;
      RECT 0.054 26.652 255.960 26.676 ;
      RECT 0.054 26.748 255.960 26.772 ;
      RECT 0.054 26.844 255.960 26.868 ;
      RECT 0.054 26.940 255.960 26.964 ;
      RECT 0.054 27.036 255.960 27.060 ;
      RECT 0.054 27.132 255.960 27.156 ;
      RECT 0.054 27.228 255.960 27.252 ;
      RECT 0.054 27.324 255.960 27.348 ;
      RECT 0.054 27.420 255.960 27.444 ;
      RECT 0.054 27.516 255.960 27.540 ;
      RECT 0.054 27.612 255.960 27.636 ;
      RECT 0.054 27.708 255.960 27.732 ;
      RECT 0.054 27.804 255.960 27.828 ;
      RECT 0.054 27.900 255.960 27.924 ;
      RECT 0.054 27.996 255.960 28.020 ;
      RECT 0.054 28.092 255.960 28.116 ;
      RECT 0.054 28.188 255.960 28.212 ;
      RECT 0.054 28.284 255.960 28.308 ;
      RECT 0.054 28.380 255.960 28.404 ;
      RECT 0.054 28.476 255.960 28.500 ;
      RECT 0.054 28.572 255.960 28.596 ;
      RECT 0.054 28.668 255.960 28.692 ;
      RECT 0.054 28.764 255.960 28.788 ;
      RECT 0.054 28.860 255.960 28.884 ;
      RECT 0.054 28.956 255.960 28.980 ;
      RECT 0.054 29.052 255.960 29.076 ;
      RECT 0.054 29.148 255.960 29.172 ;
      RECT 0.054 29.244 255.960 29.268 ;
      RECT 0.054 29.340 255.960 29.364 ;
      RECT 0.054 29.436 255.960 29.460 ;
      RECT 0.054 29.532 255.960 29.556 ;
      RECT 0.054 29.628 255.960 29.652 ;
      RECT 0.054 29.724 255.960 29.748 ;
      RECT 0.054 29.820 255.960 29.844 ;
      RECT 0.054 29.916 255.960 29.940 ;
      RECT 0.054 30.012 255.960 30.036 ;
      RECT 0.054 30.108 255.960 30.132 ;
      RECT 0.054 30.204 255.960 30.228 ;
      RECT 0.054 30.300 255.960 30.324 ;
      RECT 0.054 30.396 255.960 30.420 ;
      RECT 0.054 30.492 255.960 30.516 ;
      RECT 0.054 30.588 255.960 30.612 ;
      RECT 0.054 30.684 255.960 30.708 ;
      RECT 0.054 30.780 255.960 30.804 ;
      RECT 0.054 30.876 255.960 30.900 ;
      RECT 0.054 30.972 255.960 30.996 ;
      RECT 0.054 31.068 255.960 31.092 ;
      RECT 0.054 31.164 255.960 31.188 ;
      RECT 0.054 31.260 255.960 31.284 ;
      RECT 0.054 31.356 255.960 31.380 ;
      RECT 0.054 31.452 255.960 31.476 ;
      RECT 0.054 31.548 255.960 31.572 ;
      RECT 0.054 31.644 255.960 31.668 ;
      RECT 0.054 31.740 255.960 31.764 ;
      RECT 0.054 31.836 255.960 31.860 ;
      RECT 0.054 31.932 255.960 31.956 ;
      RECT 0.054 32.028 255.960 32.052 ;
      RECT 0.054 32.124 255.960 32.148 ;
      RECT 0.054 32.220 255.960 32.244 ;
      RECT 0.054 32.316 255.960 32.340 ;
      RECT 0.054 32.412 255.960 32.436 ;
      RECT 0.054 32.508 255.960 32.532 ;
      RECT 0.054 32.604 255.960 32.628 ;
      RECT 0.054 32.700 255.960 32.724 ;
      RECT 0.054 32.796 255.960 32.820 ;
      RECT 0.054 32.892 255.960 32.916 ;
      RECT 0.054 32.988 255.960 33.012 ;
      RECT 0.054 33.084 255.960 33.108 ;
      RECT 0.054 33.180 255.960 33.204 ;
      RECT 0.054 33.276 255.960 33.300 ;
      RECT 0.054 33.372 255.960 33.396 ;
      RECT 0.054 33.468 255.960 33.492 ;
      RECT 0.054 33.564 255.960 33.588 ;
      RECT 0.054 33.660 255.960 33.684 ;
      RECT 0.054 33.756 255.960 33.780 ;
      RECT 0.054 33.852 255.960 33.876 ;
      RECT 0.054 33.948 255.960 33.972 ;
      RECT 0.054 34.044 255.960 34.068 ;
      RECT 0.054 34.140 255.960 34.164 ;
      RECT 0.054 34.236 255.960 34.260 ;
      RECT 0.054 34.332 255.960 34.356 ;
      RECT 0.054 34.428 255.960 34.452 ;
      RECT 0.054 34.524 255.960 34.548 ;
      RECT 0.054 34.620 255.960 34.644 ;
      RECT 0.054 34.716 255.960 34.740 ;
      RECT 0.054 34.812 255.960 34.836 ;
      RECT 0.054 34.908 255.960 34.932 ;
      RECT 0.054 35.004 255.960 35.028 ;
      RECT 0.054 35.100 255.960 35.124 ;
      RECT 0.054 35.196 255.960 35.220 ;
      RECT 0.054 35.292 255.960 35.316 ;
      RECT 0.054 35.388 255.960 35.412 ;
      RECT 0.054 35.484 255.960 35.508 ;
      RECT 0.054 35.580 255.960 35.604 ;
      RECT 0.054 35.676 255.960 35.700 ;
      RECT 0.054 35.772 255.960 35.796 ;
      RECT 0.054 35.868 255.960 35.892 ;
      RECT 0.054 35.964 255.960 35.988 ;
      RECT 0.054 36.060 255.960 36.084 ;
      RECT 0.054 36.156 255.960 36.180 ;
      RECT 0.054 36.252 255.960 36.276 ;
      RECT 0.054 36.348 255.960 36.372 ;
      RECT 0.054 36.444 255.960 36.468 ;
      RECT 0.054 36.540 255.960 36.564 ;
      RECT 0.054 36.636 255.960 36.660 ;
      RECT 0.054 36.732 255.960 36.756 ;
      RECT 0.054 36.828 255.960 36.852 ;
      RECT 0.054 36.924 255.960 36.948 ;
      RECT 0.054 37.020 255.960 37.044 ;
      RECT 0.054 37.116 255.960 37.140 ;
      RECT 0.054 37.212 255.960 37.236 ;
      RECT 0.054 37.308 255.960 37.332 ;
      RECT 0.054 37.404 255.960 37.428 ;
      RECT 0.054 37.500 255.960 37.524 ;
      RECT 0.054 37.596 255.960 37.620 ;
      RECT 0.054 37.692 255.960 37.716 ;
      RECT 0.054 37.788 255.960 37.812 ;
      RECT 0.054 37.884 255.960 37.908 ;
      RECT 0.054 37.980 255.960 38.004 ;
      RECT 0.054 38.076 255.960 38.100 ;
      RECT 0.054 38.172 255.960 38.196 ;
      RECT 0.054 38.268 255.960 38.292 ;
      RECT 0.054 38.364 255.960 38.388 ;
      RECT 0.054 38.460 255.960 38.484 ;
      RECT 0.054 38.556 255.960 38.580 ;
      RECT 0.054 38.652 255.960 38.676 ;
      RECT 0.054 38.748 255.960 38.772 ;
      RECT 0.054 38.844 255.960 38.868 ;
      RECT 0.054 38.940 255.960 38.964 ;
      RECT 0.054 39.036 255.960 39.060 ;
      RECT 0.054 39.132 255.960 39.156 ;
      RECT 0.054 39.228 255.960 39.252 ;
      RECT 0.054 39.324 255.960 39.348 ;
      RECT 0.054 39.420 255.960 39.444 ;
      RECT 0.054 39.516 255.960 39.540 ;
      RECT 0.054 39.612 255.960 39.636 ;
      RECT 0.054 39.708 255.960 39.732 ;
      RECT 0.054 39.804 255.960 39.828 ;
      RECT 0.054 39.900 255.960 39.924 ;
      RECT 0.054 39.996 255.960 40.020 ;
      RECT 0.054 40.092 255.960 40.116 ;
      RECT 0.054 40.188 255.960 40.212 ;
      RECT 0.054 40.284 255.960 40.308 ;
      RECT 0.054 40.380 255.960 40.404 ;
      RECT 0.054 40.476 255.960 40.500 ;
      RECT 0.054 40.572 255.960 40.596 ;
      RECT 0.054 40.668 255.960 40.692 ;
      RECT 0.054 40.764 255.960 40.788 ;
      RECT 0.054 40.860 255.960 40.884 ;
      RECT 0.054 40.956 255.960 40.980 ;
      RECT 0.054 41.052 255.960 41.076 ;
      RECT 0.054 41.148 255.960 41.172 ;
      RECT 0.054 41.244 255.960 41.268 ;
      RECT 0.054 41.340 255.960 41.364 ;
      RECT 0.054 41.436 255.960 41.460 ;
      RECT 0.054 41.532 255.960 41.556 ;
      RECT 0.054 41.628 255.960 41.652 ;
      RECT 0.054 41.724 255.960 41.748 ;
      RECT 0.054 41.820 255.960 41.844 ;
      RECT 0.054 41.916 255.960 41.940 ;
      RECT 0.054 42.012 255.960 42.036 ;
      RECT 0.054 42.108 255.960 42.132 ;
      RECT 0.054 42.204 255.960 42.228 ;
      RECT 0.054 42.300 255.960 42.324 ;
      RECT 0.054 42.396 255.960 42.420 ;
      RECT 0.054 42.492 255.960 42.516 ;
      RECT 0.054 42.588 255.960 42.612 ;
      RECT 0.054 42.684 255.960 42.708 ;
      RECT 0.054 42.780 255.960 42.804 ;
      RECT 0.054 42.876 255.960 42.900 ;
      RECT 0.054 42.972 255.960 42.996 ;
      RECT 0.054 43.068 255.960 43.092 ;
      RECT 0.054 43.164 255.960 43.188 ;
      RECT 0.054 43.260 255.960 43.284 ;
      RECT 0.054 43.356 255.960 43.380 ;
      RECT 0.054 43.452 255.960 43.476 ;
      RECT 0.054 43.548 255.960 43.572 ;
      RECT 0.054 43.644 255.960 43.668 ;
      RECT 0.054 43.740 255.960 43.764 ;
      RECT 0.054 43.836 255.960 43.860 ;
      RECT 0.054 43.932 255.960 43.956 ;
      RECT 0.054 44.028 255.960 44.052 ;
      RECT 0.054 44.124 255.960 44.148 ;
      RECT 0.054 44.220 255.960 44.244 ;
      RECT 0.054 44.316 255.960 44.340 ;
      RECT 0.054 44.412 255.960 44.436 ;
      RECT 0.054 44.508 255.960 44.532 ;
      RECT 0.054 44.604 255.960 44.628 ;
      RECT 0.054 44.700 255.960 44.724 ;
      RECT 0.054 44.796 255.960 44.820 ;
      RECT 0.054 44.892 255.960 44.916 ;
      RECT 0.054 44.988 255.960 45.012 ;
      RECT 0.054 45.084 255.960 45.108 ;
      RECT 0.054 45.180 255.960 45.204 ;
      RECT 0.054 45.276 255.960 45.300 ;
      RECT 0.054 45.372 255.960 45.396 ;
      RECT 0.054 45.468 255.960 45.492 ;
      RECT 0.054 45.564 255.960 45.588 ;
      RECT 0.054 45.660 255.960 45.684 ;
      RECT 0.054 45.756 255.960 45.780 ;
      RECT 0.054 45.852 255.960 45.876 ;
      RECT 0.054 45.948 255.960 45.972 ;
      RECT 0.054 46.044 255.960 46.068 ;
      RECT 0.054 46.140 255.960 46.164 ;
      RECT 0.054 46.236 255.960 46.260 ;
      RECT 0.054 46.332 255.960 46.356 ;
      RECT 0.054 46.428 255.960 46.452 ;
      RECT 0.054 46.524 255.960 46.548 ;
      RECT 0.054 46.620 255.960 46.644 ;
      RECT 0.054 46.716 255.960 46.740 ;
      RECT 0.054 46.812 255.960 46.836 ;
      RECT 0.054 46.908 255.960 46.932 ;
      RECT 0.054 47.004 255.960 47.028 ;
      RECT 0.054 47.100 255.960 47.124 ;
      RECT 0.054 47.196 255.960 47.220 ;
      RECT 0.054 47.292 255.960 47.316 ;
      RECT 0.054 47.388 255.960 47.412 ;
      RECT 0.054 47.484 255.960 47.508 ;
      RECT 0.054 47.580 255.960 47.604 ;
      RECT 0.054 47.676 255.960 47.700 ;
      RECT 0.054 47.772 255.960 47.796 ;
      RECT 0.054 47.868 255.960 47.892 ;
      RECT 0.054 47.964 255.960 47.988 ;
      RECT 0.054 48.060 255.960 48.084 ;
      RECT 0.054 48.156 255.960 48.180 ;
      RECT 0.054 48.252 255.960 48.276 ;
      RECT 0.054 48.348 255.960 48.372 ;
      RECT 0.054 48.444 255.960 48.468 ;
      RECT 0.054 48.540 255.960 48.564 ;
      RECT 0.054 48.636 255.960 48.660 ;
      RECT 0.054 48.732 255.960 48.756 ;
      RECT 0.054 48.828 255.960 48.852 ;
      RECT 0.054 48.924 255.960 48.948 ;
      RECT 0.054 49.020 255.960 49.044 ;
      RECT 0.054 49.116 255.960 49.140 ;
      RECT 0.054 49.212 255.960 49.236 ;
      RECT 0.054 49.308 255.960 49.332 ;
      RECT 0.054 49.404 255.960 49.428 ;
      RECT 0.054 49.500 255.960 49.524 ;
      RECT 0.054 49.596 255.960 49.620 ;
      RECT 0.054 49.692 255.960 49.716 ;
      RECT 0.054 49.788 255.960 49.812 ;
      RECT 0.054 49.884 255.960 49.908 ;
      RECT 0.054 49.980 255.960 50.004 ;
      RECT 0.054 50.076 255.960 50.100 ;
      RECT 0.054 50.172 255.960 50.196 ;
      RECT 0.054 50.268 255.960 50.292 ;
      RECT 0.054 50.364 255.960 50.388 ;
      RECT 0.054 50.460 255.960 50.484 ;
      RECT 0.054 50.556 255.960 50.580 ;
      RECT 0.054 50.652 255.960 50.676 ;
      RECT 0.054 50.748 255.960 50.772 ;
      RECT 0.054 50.844 255.960 50.868 ;
      RECT 0.054 50.940 255.960 50.964 ;
      RECT 0.054 51.036 255.960 51.060 ;
      RECT 0.054 51.132 255.960 51.156 ;
      RECT 0.054 51.228 255.960 51.252 ;
      RECT 0.054 51.324 255.960 51.348 ;
      RECT 0.054 51.420 255.960 51.444 ;
      RECT 0.054 51.516 255.960 51.540 ;
      RECT 0.054 51.612 255.960 51.636 ;
      RECT 0.054 51.708 255.960 51.732 ;
      RECT 0.054 51.804 255.960 51.828 ;
      RECT 0.054 51.900 255.960 51.924 ;
      RECT 0.054 51.996 255.960 52.020 ;
      RECT 0.054 52.092 255.960 52.116 ;
      RECT 0.054 52.188 255.960 52.212 ;
      RECT 0.054 52.284 255.960 52.308 ;
      RECT 0.054 52.380 255.960 52.404 ;
      RECT 0.054 52.476 255.960 52.500 ;
      RECT 0.054 52.572 255.960 52.596 ;
      RECT 0.054 52.668 255.960 52.692 ;
      RECT 0.054 52.764 255.960 52.788 ;
      RECT 0.054 52.860 255.960 52.884 ;
      RECT 0.054 52.956 255.960 52.980 ;
      RECT 0.054 53.052 255.960 53.076 ;
      RECT 0.054 53.148 255.960 53.172 ;
      RECT 0.054 53.244 255.960 53.268 ;
      RECT 0.054 53.340 255.960 53.364 ;
      RECT 0.054 53.436 255.960 53.460 ;
      RECT 0.054 53.532 255.960 53.556 ;
      RECT 0.054 53.628 255.960 53.652 ;
      RECT 0.054 53.724 255.960 53.748 ;
      RECT 0.054 53.820 255.960 53.844 ;
      RECT 0.054 53.916 255.960 53.940 ;
      RECT 0.054 54.012 255.960 54.036 ;
      RECT 0.054 54.108 255.960 54.132 ;
      RECT 0.054 54.204 255.960 54.228 ;
      RECT 0.054 54.300 255.960 54.324 ;
      RECT 0.054 54.396 255.960 54.420 ;
      RECT 0.054 54.492 255.960 54.516 ;
      RECT 0.054 54.588 255.960 54.612 ;
      RECT 0.054 54.684 255.960 54.708 ;
      RECT 0.054 54.780 255.960 54.804 ;
      RECT 0.054 54.876 255.960 54.900 ;
      RECT 0.054 54.972 255.960 54.996 ;
      RECT 0.054 55.068 255.960 55.092 ;
      RECT 0.054 55.164 255.960 55.188 ;
      RECT 0.054 55.260 255.960 55.284 ;
      RECT 0.054 55.356 255.960 55.380 ;
      RECT 0.054 55.452 255.960 55.476 ;
      RECT 0.054 55.548 255.960 55.572 ;
      RECT 0.054 55.644 255.960 55.668 ;
      RECT 0.054 55.740 255.960 55.764 ;
      RECT 0.054 55.836 255.960 55.860 ;
      RECT 0.054 55.932 255.960 55.956 ;
      RECT 0.054 56.028 255.960 56.052 ;
      RECT 0.054 56.124 255.960 56.148 ;
      RECT 0.054 56.220 255.960 56.244 ;
      RECT 0.054 56.316 255.960 56.340 ;
      RECT 0.054 56.412 255.960 56.436 ;
      RECT 0.054 56.508 255.960 56.532 ;
      RECT 0.054 56.604 255.960 56.628 ;
      RECT 0.054 56.700 255.960 56.724 ;
      RECT 0.054 56.796 255.960 56.820 ;
      RECT 0.054 56.892 255.960 56.916 ;
      RECT 0.054 56.988 255.960 57.012 ;
      RECT 0.054 57.084 255.960 57.108 ;
      RECT 0.054 57.180 255.960 57.204 ;
      RECT 0.054 57.276 255.960 57.300 ;
      RECT 0.054 57.372 255.960 57.396 ;
      RECT 0.054 57.468 255.960 57.492 ;
      RECT 0.054 57.564 255.960 57.588 ;
      RECT 0.054 57.660 255.960 57.684 ;
      RECT 0.054 57.756 255.960 57.780 ;
      RECT 0.054 57.852 255.960 57.876 ;
      RECT 0.054 57.948 255.960 57.972 ;
      RECT 0.054 58.044 255.960 58.068 ;
      RECT 0.054 58.140 255.960 58.164 ;
      RECT 0.054 58.236 255.960 58.260 ;
      RECT 0.054 58.332 255.960 58.356 ;
      RECT 0.054 58.428 255.960 58.452 ;
      RECT 0.054 58.524 255.960 58.548 ;
      RECT 0.054 58.620 255.960 58.644 ;
      RECT 0.054 58.716 255.960 58.740 ;
      RECT 0.054 58.812 255.960 58.836 ;
      RECT 0.054 58.908 255.960 58.932 ;
      RECT 0.054 59.004 255.960 59.028 ;
      RECT 0.054 59.100 255.960 59.124 ;
      RECT 0.054 59.196 255.960 59.220 ;
      RECT 0.054 59.292 255.960 59.316 ;
      RECT 0.054 59.388 255.960 59.412 ;
      RECT 0.054 59.484 255.960 59.508 ;
      RECT 0.054 59.580 255.960 59.604 ;
      RECT 0.054 59.676 255.960 59.700 ;
      RECT 0.054 59.772 255.960 59.796 ;
      RECT 0.054 59.868 255.960 59.892 ;
      RECT 0.054 59.964 255.960 59.988 ;
      RECT 0.054 60.060 255.960 60.084 ;
      RECT 0.054 60.156 255.960 60.180 ;
      RECT 0.054 60.252 255.960 60.276 ;
      RECT 0.054 60.348 255.960 60.372 ;
      RECT 0.054 60.444 255.960 60.468 ;
      RECT 0.054 60.540 255.960 60.564 ;
      RECT 0.054 60.636 255.960 60.660 ;
      RECT 0.054 60.732 255.960 60.756 ;
      RECT 0.054 60.828 255.960 60.852 ;
      RECT 0.054 60.924 255.960 60.948 ;
      RECT 0.054 61.020 255.960 61.044 ;
      RECT 0.054 61.116 255.960 61.140 ;
      RECT 0.054 61.212 255.960 61.236 ;
      RECT 0.054 61.308 255.960 61.332 ;
      RECT 0.054 61.404 255.960 61.428 ;
      RECT 0.054 61.500 255.960 61.524 ;
      RECT 0.054 61.596 255.960 61.620 ;
      RECT 0.054 61.692 255.960 61.716 ;
      RECT 0.054 61.788 255.960 61.812 ;
      RECT 0.054 61.884 255.960 61.908 ;
      RECT 0.054 61.980 255.960 62.004 ;
      RECT 0.054 62.076 255.960 62.100 ;
      RECT 0.054 62.172 255.960 62.196 ;
      RECT 0.054 62.268 255.960 62.292 ;
      RECT 0.054 62.364 255.960 62.388 ;
      RECT 0.054 62.460 255.960 62.484 ;
      RECT 0.054 62.556 255.960 62.580 ;
      RECT 0.054 62.652 255.960 62.676 ;
      RECT 0.054 62.748 255.960 62.772 ;
      RECT 0.054 62.844 255.960 62.868 ;
      RECT 0.054 62.940 255.960 62.964 ;
      RECT 0.054 63.036 255.960 63.060 ;
      RECT 0.054 63.132 255.960 63.156 ;
      RECT 0.054 63.228 255.960 63.252 ;
      RECT 0.054 63.324 255.960 63.348 ;
      RECT 0.054 63.420 255.960 63.444 ;
      RECT 0.054 63.516 255.960 63.540 ;
      RECT 0.054 63.612 255.960 63.636 ;
      RECT 0.054 63.708 255.960 63.732 ;
      RECT 0.054 63.804 255.960 63.828 ;
      RECT 0.054 63.900 255.960 63.924 ;
      RECT 0.054 63.996 255.960 64.020 ;
      RECT 0.054 64.092 255.960 64.116 ;
      RECT 0.054 64.188 255.960 64.212 ;
      RECT 0.054 64.284 255.960 64.308 ;
      RECT 0.054 64.380 255.960 64.404 ;
      RECT 0.054 64.476 255.960 64.500 ;
      RECT 0.054 64.572 255.960 64.596 ;
      RECT 0.054 64.668 255.960 64.692 ;
      RECT 0.054 64.764 255.960 64.788 ;
      RECT 0.054 64.860 255.960 64.884 ;
      RECT 0.054 64.956 255.960 64.980 ;
      RECT 0.054 65.052 255.960 65.076 ;
      RECT 0.054 65.148 255.960 65.172 ;
      RECT 0.054 65.244 255.960 65.268 ;
      RECT 0.054 65.340 255.960 65.364 ;
      RECT 0.054 65.436 255.960 65.460 ;
      RECT 0.054 65.532 255.960 65.556 ;
      RECT 0.054 65.628 255.960 65.652 ;
      RECT 0.054 65.724 255.960 65.748 ;
      RECT 0.054 65.820 255.960 65.844 ;
      RECT 0.054 65.916 255.960 65.940 ;
      RECT 0.054 66.012 255.960 66.036 ;
      RECT 0.054 66.108 255.960 66.132 ;
      RECT 0.054 66.204 255.960 66.228 ;
      RECT 0.054 66.300 255.960 66.324 ;
      RECT 0.054 66.396 255.960 66.420 ;
      RECT 0.054 66.492 255.960 66.516 ;
      RECT 0.054 66.588 255.960 66.612 ;
      RECT 0.054 66.684 255.960 66.708 ;
      RECT 0.054 66.780 255.960 66.804 ;
      RECT 0.054 66.876 255.960 66.900 ;
      RECT 0.054 66.972 255.960 66.996 ;
      RECT 0.054 67.068 255.960 67.092 ;
      RECT 0.054 67.164 255.960 67.188 ;
      RECT 0.054 67.260 255.960 67.284 ;
      RECT 0.054 67.356 255.960 67.380 ;
      RECT 0.054 67.452 255.960 67.476 ;
      RECT 0.054 67.548 255.960 67.572 ;
      RECT 0.054 67.644 255.960 67.668 ;
      RECT 0.054 67.740 255.960 67.764 ;
      RECT 0.054 67.836 255.960 67.860 ;
      RECT 0.054 67.932 255.960 67.956 ;
      RECT 0.054 68.028 255.960 68.052 ;
      RECT 0.054 68.124 255.960 68.148 ;
      RECT 0.054 68.220 255.960 68.244 ;
      RECT 0.054 68.316 255.960 68.340 ;
      RECT 0.054 68.412 255.960 68.436 ;
      RECT 0.054 68.508 255.960 68.532 ;
      RECT 0.054 68.604 255.960 68.628 ;
      RECT 0.054 68.700 255.960 68.724 ;
      RECT 0.054 68.796 255.960 68.820 ;
      RECT 0.054 68.892 255.960 68.916 ;
      RECT 0.054 68.988 255.960 69.012 ;
      RECT 0.054 69.084 255.960 69.108 ;
      RECT 0.054 69.180 255.960 69.204 ;
      RECT 0.054 69.276 255.960 69.300 ;
      RECT 0.054 69.372 255.960 69.396 ;
      RECT 0.054 69.468 255.960 69.492 ;
      RECT 0.054 69.564 255.960 69.588 ;
      RECT 0.054 69.660 255.960 69.684 ;
      RECT 0.054 69.756 255.960 69.780 ;
      RECT 0.054 69.852 255.960 69.876 ;
      RECT 0.054 69.948 255.960 69.972 ;
      RECT 0.054 70.044 255.960 70.068 ;
      RECT 0.054 70.140 255.960 70.164 ;
      RECT 0.054 70.236 255.960 70.260 ;
      RECT 0.054 70.332 255.960 70.356 ;
      RECT 0.054 70.428 255.960 70.452 ;
      RECT 0.054 70.524 255.960 70.548 ;
      RECT 0.054 70.620 255.960 70.644 ;
      RECT 0.054 70.716 255.960 70.740 ;
      RECT 0.054 70.812 255.960 70.836 ;
      RECT 0.054 70.908 255.960 70.932 ;
      RECT 0.054 71.004 255.960 71.028 ;
      RECT 0.054 71.100 255.960 71.124 ;
      RECT 0.054 71.196 255.960 71.220 ;
      RECT 0.054 71.292 255.960 71.316 ;
      RECT 0.054 71.388 255.960 71.412 ;
      RECT 0.054 71.484 255.960 71.508 ;
      RECT 0.054 71.580 255.960 71.604 ;
      RECT 0.054 71.676 255.960 71.700 ;
      RECT 0.054 71.772 255.960 71.796 ;
      RECT 0.054 71.868 255.960 71.892 ;
      RECT 0.054 71.964 255.960 71.988 ;
      RECT 0.054 72.060 255.960 72.084 ;
      RECT 0.054 72.156 255.960 72.180 ;
      RECT 0.054 72.252 255.960 72.276 ;
      RECT 0.054 72.348 255.960 72.372 ;
      RECT 0.054 72.444 255.960 72.468 ;
      RECT 0.054 72.540 255.960 72.564 ;
      RECT 0.054 72.636 255.960 72.660 ;
      RECT 0.054 72.732 255.960 72.756 ;
      RECT 0.054 72.828 255.960 72.852 ;
      RECT 0.054 72.924 255.960 72.948 ;
      RECT 0.054 73.020 255.960 73.044 ;
      RECT 0.054 73.116 255.960 73.140 ;
      RECT 0.054 73.212 255.960 73.236 ;
      RECT 0.054 73.308 255.960 73.332 ;
      RECT 0.054 73.404 255.960 73.428 ;
      RECT 0.054 73.500 255.960 73.524 ;
      RECT 0.054 73.596 255.960 73.620 ;
      RECT 0.054 73.692 255.960 73.716 ;
      RECT 0.054 73.788 255.960 73.812 ;
      RECT 0.054 73.884 255.960 73.908 ;
      RECT 0.054 73.980 255.960 74.004 ;
      RECT 0.054 74.076 255.960 74.100 ;
      RECT 0.054 74.172 255.960 74.196 ;
      RECT 0.054 74.268 255.960 74.292 ;
      RECT 0.054 74.364 255.960 74.388 ;
      RECT 0.054 74.460 255.960 74.484 ;
      RECT 0.054 74.556 255.960 74.580 ;
      RECT 0.054 74.652 255.960 74.676 ;
      RECT 0.054 74.748 255.960 74.772 ;
      RECT 0.054 74.844 255.960 74.868 ;
      RECT 0.054 74.940 255.960 74.964 ;
      RECT 0.054 75.036 255.960 75.060 ;
      RECT 0.054 75.132 255.960 75.156 ;
      RECT 0.054 75.228 255.960 75.252 ;
      RECT 0.054 75.324 255.960 75.348 ;
      RECT 0.054 75.420 255.960 75.444 ;
      RECT 0.054 75.516 255.960 75.540 ;
      RECT 0.054 75.612 255.960 75.636 ;
      RECT 0.054 75.708 255.960 75.732 ;
      RECT 0.054 75.804 255.960 75.828 ;
      RECT 0.054 75.900 255.960 75.924 ;
      RECT 0.054 75.996 255.960 76.020 ;
      RECT 0.054 76.092 255.960 76.116 ;
      RECT 0.054 76.188 255.960 76.212 ;
      RECT 0.054 76.284 255.960 76.308 ;
      RECT 0.054 76.380 255.960 76.404 ;
      RECT 0.054 76.476 255.960 76.500 ;
      RECT 0.054 76.572 255.960 76.596 ;
      RECT 0.054 76.668 255.960 76.692 ;
      RECT 0.054 76.764 255.960 76.788 ;
      RECT 0.054 76.860 255.960 76.884 ;
      RECT 0.054 76.956 255.960 76.980 ;
      RECT 0.054 77.052 255.960 77.076 ;
      RECT 0.054 77.148 255.960 77.172 ;
      RECT 0.054 77.244 255.960 77.268 ;
      RECT 0.054 77.340 255.960 77.364 ;
      RECT 0.054 77.436 255.960 77.460 ;
      RECT 0.054 77.532 255.960 77.556 ;
      RECT 0.054 77.628 255.960 77.652 ;
      RECT 0.054 77.724 255.960 77.748 ;
      RECT 0.054 77.820 255.960 77.844 ;
      RECT 0.054 77.916 255.960 77.940 ;
      RECT 0.054 78.012 255.960 78.036 ;
      RECT 0.054 78.108 255.960 78.132 ;
      RECT 0.054 78.204 255.960 78.228 ;
      RECT 0.054 78.300 255.960 78.324 ;
      RECT 0.054 78.396 255.960 78.420 ;
      RECT 0.054 78.492 255.960 78.516 ;
      RECT 0.054 78.588 255.960 78.612 ;
      RECT 0.054 78.684 255.960 78.708 ;
      RECT 0.054 78.780 255.960 78.804 ;
      RECT 0.054 78.876 255.960 78.900 ;
      RECT 0.054 78.972 255.960 78.996 ;
      RECT 0.054 79.068 255.960 79.092 ;
      RECT 0.054 79.164 255.960 79.188 ;
      RECT 0.054 79.260 255.960 79.284 ;
      RECT 0.054 79.356 255.960 79.380 ;
      RECT 0.054 79.452 255.960 79.476 ;
      RECT 0.054 79.548 255.960 79.572 ;
      RECT 0.054 79.644 255.960 79.668 ;
      RECT 0.054 79.740 255.960 79.764 ;
      RECT 0.054 79.836 255.960 79.860 ;
      RECT 0.054 79.932 255.960 79.956 ;
      RECT 0.054 80.028 255.960 80.052 ;
      RECT 0.054 80.124 255.960 80.148 ;
      RECT 0.054 80.220 255.960 80.244 ;
      RECT 0.054 80.316 255.960 80.340 ;
      RECT 0.054 80.412 255.960 80.436 ;
      RECT 0.054 80.508 255.960 80.532 ;
      RECT 0.054 80.604 255.960 80.628 ;
      RECT 0.054 80.700 255.960 80.724 ;
      RECT 0.054 80.796 255.960 80.820 ;
      RECT 0.054 80.892 255.960 80.916 ;
      RECT 0.054 80.988 255.960 81.012 ;
      RECT 0.054 81.084 255.960 81.108 ;
      RECT 0.054 81.180 255.960 81.204 ;
      RECT 0.054 81.276 255.960 81.300 ;
      RECT 0.054 81.372 255.960 81.396 ;
      RECT 0.054 81.468 255.960 81.492 ;
      RECT 0.054 81.564 255.960 81.588 ;
      RECT 0.054 81.660 255.960 81.684 ;
      RECT 0.054 81.756 255.960 81.780 ;
      RECT 0.054 81.852 255.960 81.876 ;
      RECT 0.054 81.948 255.960 81.972 ;
      RECT 0.054 82.044 255.960 82.068 ;
      RECT 0.054 82.140 255.960 82.164 ;
      RECT 0.054 82.236 255.960 82.260 ;
      RECT 0.054 82.332 255.960 82.356 ;
      RECT 0.054 82.428 255.960 82.452 ;
      RECT 0.054 82.524 255.960 82.548 ;
      RECT 0.054 82.620 255.960 82.644 ;
      RECT 0.054 82.716 255.960 82.740 ;
      RECT 0.054 82.812 255.960 82.836 ;
      RECT 0.054 82.908 255.960 82.932 ;
      RECT 0.054 83.004 255.960 83.028 ;
      RECT 0.054 83.100 255.960 83.124 ;
      RECT 0.054 83.196 255.960 83.220 ;
      RECT 0.054 83.292 255.960 83.316 ;
      RECT 0.054 83.388 255.960 83.412 ;
      RECT 0.054 83.484 255.960 83.508 ;
      RECT 0.054 83.580 255.960 83.604 ;
      RECT 0.054 83.676 255.960 83.700 ;
      RECT 0.054 83.772 255.960 83.796 ;
      RECT 0.054 83.868 255.960 83.892 ;
      RECT 0.054 83.964 255.960 83.988 ;
      RECT 0.054 84.060 255.960 84.084 ;
      RECT 0.054 84.156 255.960 84.180 ;
      RECT 0.054 84.252 255.960 84.276 ;
      RECT 0.054 84.348 255.960 84.372 ;
      RECT 0.054 84.444 255.960 84.468 ;
      RECT 0.054 84.540 255.960 84.564 ;
      RECT 0.054 84.636 255.960 84.660 ;
      RECT 0.054 84.732 255.960 84.756 ;
      RECT 0.054 84.828 255.960 84.852 ;
      RECT 0.054 84.924 255.960 84.948 ;
      RECT 0.054 85.020 255.960 85.044 ;
      RECT 0.054 85.116 255.960 85.140 ;
      RECT 0.054 85.212 255.960 85.236 ;
      RECT 0.054 85.308 255.960 85.332 ;
      RECT 0.054 85.404 255.960 85.428 ;
      RECT 0.054 85.500 255.960 85.524 ;
      RECT 0.054 85.596 255.960 85.620 ;
      RECT 0.054 85.692 255.960 85.716 ;
      RECT 0.054 85.788 255.960 85.812 ;
      RECT 0.054 85.884 255.960 85.908 ;
      RECT 0.054 85.980 255.960 86.004 ;
      RECT 0.054 86.076 255.960 86.100 ;
      RECT 0.054 86.172 255.960 86.196 ;
      RECT 0.054 86.268 255.960 86.292 ;
      RECT 0.054 86.364 255.960 86.388 ;
      RECT 0.054 86.460 255.960 86.484 ;
      RECT 0.054 86.556 255.960 86.580 ;
      RECT 0.054 86.652 255.960 86.676 ;
      RECT 0.054 86.748 255.960 86.772 ;
      RECT 0.054 86.844 255.960 86.868 ;
      RECT 0.054 86.940 255.960 86.964 ;
      RECT 0.054 87.036 255.960 87.060 ;
      RECT 0.054 87.132 255.960 87.156 ;
      RECT 0.054 87.228 255.960 87.252 ;
      RECT 0.054 87.324 255.960 87.348 ;
      RECT 0.054 87.420 255.960 87.444 ;
      RECT 0.054 87.516 255.960 87.540 ;
      RECT 0.054 87.612 255.960 87.636 ;
      RECT 0.054 87.708 255.960 87.732 ;
      RECT 0.054 87.804 255.960 87.828 ;
      RECT 0.054 87.900 255.960 87.924 ;
      RECT 0.054 87.996 255.960 88.020 ;
      RECT 0.054 88.092 255.960 88.116 ;
      RECT 0.054 88.188 255.960 88.212 ;
      RECT 0.054 88.284 255.960 88.308 ;
      RECT 0.054 88.380 255.960 88.404 ;
      RECT 0.054 88.476 255.960 88.500 ;
      RECT 0.054 88.572 255.960 88.596 ;
      RECT 0.054 88.668 255.960 88.692 ;
      RECT 0.054 88.764 255.960 88.788 ;
      RECT 0.054 88.860 255.960 88.884 ;
      RECT 0.054 88.956 255.960 88.980 ;
      RECT 0.054 89.052 255.960 89.076 ;
      RECT 0.054 89.148 255.960 89.172 ;
      RECT 0.054 89.244 255.960 89.268 ;
      RECT 0.054 89.340 255.960 89.364 ;
      RECT 0.054 89.436 255.960 89.460 ;
      RECT 0.054 89.532 255.960 89.556 ;
      RECT 0.054 89.628 255.960 89.652 ;
      RECT 0.054 89.724 255.960 89.748 ;
      RECT 0.054 89.820 255.960 89.844 ;
      RECT 0.054 89.916 255.960 89.940 ;
      RECT 0.054 90.012 255.960 90.036 ;
      RECT 0.054 90.108 255.960 90.132 ;
      RECT 0.054 90.204 255.960 90.228 ;
      RECT 0.054 90.300 255.960 90.324 ;
      RECT 0.054 90.396 255.960 90.420 ;
      RECT 0.054 90.492 255.960 90.516 ;
      RECT 0.054 90.588 255.960 90.612 ;
      RECT 0.054 90.684 255.960 90.708 ;
      RECT 0.054 90.780 255.960 90.804 ;
      RECT 0.054 90.876 255.960 90.900 ;
      RECT 0.054 90.972 255.960 90.996 ;
      RECT 0.054 91.068 255.960 91.092 ;
      RECT 0.054 91.164 255.960 91.188 ;
      RECT 0.054 91.260 255.960 91.284 ;
      RECT 0.054 91.356 255.960 91.380 ;
      RECT 0.054 91.452 255.960 91.476 ;
      RECT 0.054 91.548 255.960 91.572 ;
      RECT 0.054 91.644 255.960 91.668 ;
      RECT 0.054 91.740 255.960 91.764 ;
      RECT 0.054 91.836 255.960 91.860 ;
      RECT 0.054 91.932 255.960 91.956 ;
      RECT 0.054 92.028 255.960 92.052 ;
      RECT 0.054 92.124 255.960 92.148 ;
      RECT 0.054 92.220 255.960 92.244 ;
      RECT 0.054 92.316 255.960 92.340 ;
      RECT 0.054 92.412 255.960 92.436 ;
      RECT 0.054 92.508 255.960 92.532 ;
      RECT 0.054 92.604 255.960 92.628 ;
      RECT 0.054 92.700 255.960 92.724 ;
      RECT 0.054 92.796 255.960 92.820 ;
      RECT 0.054 92.892 255.960 92.916 ;
      RECT 0.054 92.988 255.960 93.012 ;
      RECT 0.054 93.084 255.960 93.108 ;
      RECT 0.054 93.180 255.960 93.204 ;
      RECT 0.054 93.276 255.960 93.300 ;
      RECT 0.054 93.372 255.960 93.396 ;
      RECT 0.054 93.468 255.960 93.492 ;
      RECT 0.054 93.564 255.960 93.588 ;
      RECT 0.054 93.660 255.960 93.684 ;
      RECT 0.054 93.756 255.960 93.780 ;
      RECT 0.054 93.852 255.960 93.876 ;
      RECT 0.054 93.948 255.960 93.972 ;
      RECT 0.054 94.044 255.960 94.068 ;
      RECT 0.054 94.140 255.960 94.164 ;
      RECT 0.054 94.236 255.960 94.260 ;
      RECT 0.054 94.332 255.960 94.356 ;
      RECT 0.054 94.428 255.960 94.452 ;
      RECT 0.054 94.524 255.960 94.548 ;
      RECT 0.054 94.620 255.960 94.644 ;
      RECT 0.054 94.716 255.960 94.740 ;
      RECT 0.054 94.812 255.960 94.836 ;
      RECT 0.054 94.908 255.960 94.932 ;
      RECT 0.054 95.004 255.960 95.028 ;
      RECT 0.054 95.100 255.960 95.124 ;
      RECT 0.054 95.196 255.960 95.220 ;
      RECT 0.054 95.292 255.960 95.316 ;
      RECT 0.054 95.388 255.960 95.412 ;
      RECT 0.054 95.484 255.960 95.508 ;
      RECT 0.054 95.580 255.960 95.604 ;
      RECT 0.054 95.676 255.960 95.700 ;
      RECT 0.054 95.772 255.960 95.796 ;
      RECT 0.054 95.868 255.960 95.892 ;
      RECT 0.054 95.964 255.960 95.988 ;
      RECT 0.054 96.060 255.960 96.084 ;
      RECT 0.054 96.156 255.960 96.180 ;
      RECT 0.054 96.252 255.960 96.276 ;
      RECT 0.054 96.348 255.960 96.372 ;
      RECT 0.054 96.444 255.960 96.468 ;
      RECT 0.054 96.540 255.960 96.564 ;
      RECT 0.054 96.636 255.960 96.660 ;
      RECT 0.054 96.732 255.960 96.756 ;
      RECT 0.054 96.828 255.960 96.852 ;
      RECT 0.054 96.924 255.960 96.948 ;
      RECT 0.054 97.020 255.960 97.044 ;
      RECT 0.054 97.116 255.960 97.140 ;
      RECT 0.054 97.212 255.960 97.236 ;
      RECT 0.054 97.308 255.960 97.332 ;
      RECT 0.054 97.404 255.960 97.428 ;
      RECT 0.054 97.500 255.960 97.524 ;
      RECT 0.054 97.596 255.960 97.620 ;
      RECT 0.054 97.692 255.960 97.716 ;
      RECT 0.054 97.788 255.960 97.812 ;
      RECT 0.054 97.884 255.960 97.908 ;
      RECT 0.054 97.980 255.960 98.004 ;
      RECT 0.054 98.076 255.960 98.100 ;
      RECT 0.054 98.172 255.960 98.196 ;
      RECT 0.054 98.268 255.960 98.292 ;
      RECT 0.054 98.364 255.960 98.388 ;
      RECT 0.054 98.460 255.960 98.484 ;
      RECT 0.054 98.556 255.960 98.580 ;
      RECT 0.054 98.652 255.960 98.676 ;
      RECT 0.054 98.748 255.960 98.772 ;
      RECT 0.054 98.844 255.960 98.868 ;
      RECT 0.054 98.940 255.960 98.964 ;
      RECT 0.054 99.036 255.960 99.060 ;
      RECT 0.054 99.132 255.960 99.156 ;
      RECT 0.054 99.228 255.960 99.252 ;
      RECT 0.054 99.324 255.960 99.348 ;
      RECT 0.054 99.420 255.960 99.444 ;
      RECT 0.054 99.516 255.960 99.540 ;
      RECT 0.054 99.612 255.960 99.636 ;
      RECT 0.054 99.708 255.960 99.732 ;
      RECT 0.054 99.804 255.960 99.828 ;
      RECT 0.054 99.900 255.960 99.924 ;
      RECT 0.054 99.996 255.960 100.020 ;
      RECT 0.054 100.092 255.960 100.116 ;
      RECT 0.054 100.188 255.960 100.212 ;
      RECT 0.054 100.284 255.960 100.308 ;
      RECT 0.054 100.380 255.960 100.404 ;
      RECT 0.054 100.476 255.960 100.500 ;
      RECT 0.054 100.572 255.960 100.596 ;
      RECT 0.054 100.668 255.960 100.692 ;
      RECT 0.054 100.764 255.960 100.788 ;
      RECT 0.054 100.860 255.960 100.884 ;
      RECT 0.054 100.956 255.960 100.980 ;
      RECT 0.054 101.052 255.960 101.076 ;
      RECT 0.054 101.148 255.960 101.172 ;
      RECT 0.054 101.244 255.960 101.268 ;
      RECT 0.054 101.340 255.960 101.364 ;
      RECT 0.054 101.436 255.960 101.460 ;
      RECT 0.054 101.532 255.960 101.556 ;
      RECT 0.054 101.628 255.960 101.652 ;
      RECT 0.054 101.724 255.960 101.748 ;
      RECT 0.054 101.820 255.960 101.844 ;
      RECT 0.054 101.916 255.960 101.940 ;
      RECT 0.054 102.012 255.960 102.036 ;
      RECT 0.054 102.108 255.960 102.132 ;
      RECT 0.054 102.204 255.960 102.228 ;
      RECT 0.054 102.300 255.960 102.324 ;
      RECT 0.054 102.396 255.960 102.420 ;
      RECT 0.054 102.492 255.960 102.516 ;
      RECT 0.054 102.588 255.960 102.612 ;
      RECT 0.054 102.684 255.960 102.708 ;
      RECT 0.054 102.780 255.960 102.804 ;
      RECT 0.054 102.876 255.960 102.900 ;
      RECT 0.054 102.972 255.960 102.996 ;
      RECT 0.054 103.068 255.960 103.092 ;
      RECT 0.054 103.164 255.960 103.188 ;
      RECT 0.054 103.260 255.960 103.284 ;
      RECT 0.054 103.356 255.960 103.380 ;
      RECT 0.054 103.452 255.960 103.476 ;
      RECT 0.054 103.548 255.960 103.572 ;
      RECT 0.054 103.644 255.960 103.668 ;
      RECT 0.054 103.740 255.960 103.764 ;
      RECT 0.054 103.836 255.960 103.860 ;
      RECT 0.054 103.932 255.960 103.956 ;
      RECT 0.054 104.028 255.960 104.052 ;
      RECT 0.054 104.124 255.960 104.148 ;
      RECT 0.054 104.220 255.960 104.244 ;
      RECT 0.054 104.316 255.960 104.340 ;
      RECT 0.054 104.412 255.960 104.436 ;
      RECT 0.054 104.508 255.960 104.532 ;
      RECT 0.054 104.604 255.960 104.628 ;
      RECT 0.054 104.700 255.960 104.724 ;
      RECT 0.054 104.796 255.960 104.820 ;
      RECT 0.054 104.892 255.960 104.916 ;
      RECT 0.054 104.988 255.960 105.012 ;
      RECT 0.054 105.084 255.960 105.108 ;
      RECT 0.054 105.180 255.960 105.204 ;
      RECT 0.054 105.276 255.960 105.300 ;
      RECT 0.054 105.372 255.960 105.396 ;
      RECT 0.054 105.468 255.960 105.492 ;
      RECT 0.054 105.564 255.960 105.588 ;
      RECT 0.054 105.660 255.960 105.684 ;
      RECT 0.054 105.756 255.960 105.780 ;
      RECT 0.054 105.852 255.960 105.876 ;
      RECT 0.054 105.948 255.960 105.972 ;
      RECT 0.054 106.044 255.960 106.068 ;
      RECT 0.054 106.140 255.960 106.164 ;
      RECT 0.054 106.236 255.960 106.260 ;
      RECT 0.054 106.332 255.960 106.356 ;
      RECT 0.054 106.428 255.960 106.452 ;
      RECT 0.054 106.524 255.960 106.548 ;
      RECT 0.054 106.620 255.960 106.644 ;
      RECT 0.054 106.716 255.960 106.740 ;
      RECT 0.054 106.812 255.960 106.836 ;
      RECT 0.054 106.908 255.960 106.932 ;
      RECT 0.054 107.004 255.960 107.028 ;
      RECT 0.054 107.100 255.960 107.124 ;
      RECT 0.054 107.196 255.960 107.220 ;
      RECT 0.054 107.292 255.960 107.316 ;
      RECT 0.054 107.388 255.960 107.412 ;
      RECT 0.054 107.484 255.960 107.508 ;
      RECT 0.054 107.580 255.960 107.604 ;
      RECT 0.054 107.676 255.960 107.700 ;
      RECT 0.054 107.772 255.960 107.796 ;
      RECT 0.054 107.868 255.960 107.892 ;
      RECT 0.054 107.964 255.960 107.988 ;
      RECT 0.054 108.060 255.960 108.084 ;
      RECT 0.054 108.156 255.960 108.180 ;
      RECT 0.054 108.252 255.960 108.276 ;
      RECT 0.054 108.348 255.960 108.372 ;
      RECT 0.054 108.444 255.960 108.468 ;
      RECT 0.054 108.540 255.960 108.564 ;
      RECT 0.054 108.636 255.960 108.660 ;
      RECT 0.054 108.732 255.960 108.756 ;
      RECT 0.054 108.828 255.960 108.852 ;
      RECT 0.054 108.924 255.960 108.948 ;
      RECT 0.054 109.020 255.960 109.044 ;
      RECT 0.054 109.116 255.960 109.140 ;
      RECT 0.054 109.212 255.960 109.236 ;
      RECT 0.054 109.308 255.960 109.332 ;
      RECT 0.054 109.404 255.960 109.428 ;
      RECT 0.054 109.500 255.960 109.524 ;
      RECT 0.054 109.596 255.960 109.620 ;
      RECT 0.054 109.692 255.960 109.716 ;
      RECT 0.054 109.788 255.960 109.812 ;
      RECT 0.054 109.884 255.960 109.908 ;
      RECT 0.054 109.980 255.960 110.004 ;
      RECT 0.054 110.076 255.960 110.100 ;
      RECT 0.054 110.172 255.960 110.196 ;
      RECT 0.054 110.268 255.960 110.292 ;
      RECT 0.054 110.364 255.960 110.388 ;
      RECT 0.054 110.460 255.960 110.484 ;
      RECT 0.054 110.556 255.960 110.580 ;
      RECT 0.054 110.652 255.960 110.676 ;
      RECT 0.054 110.748 255.960 110.772 ;
      RECT 0.054 110.844 255.960 110.868 ;
      RECT 0.054 110.940 255.960 110.964 ;
      RECT 0.054 111.036 255.960 111.060 ;
      RECT 0.054 111.132 255.960 111.156 ;
      RECT 0.054 111.228 255.960 111.252 ;
      RECT 0.054 111.324 255.960 111.348 ;
      RECT 0.054 111.420 255.960 111.444 ;
      RECT 0.054 111.516 255.960 111.540 ;
      RECT 0.054 111.612 255.960 111.636 ;
      RECT 0.054 111.708 255.960 111.732 ;
      RECT 0.054 111.804 255.960 111.828 ;
      RECT 0.054 111.900 255.960 111.924 ;
      RECT 0.054 111.996 255.960 112.020 ;
      RECT 0.054 112.092 255.960 112.116 ;
      RECT 0.054 112.188 255.960 112.212 ;
      RECT 0.054 112.284 255.960 112.308 ;
      RECT 0.054 112.380 255.960 112.404 ;
      RECT 0.054 112.476 255.960 112.500 ;
      RECT 0.054 112.572 255.960 112.596 ;
      RECT 0.054 112.668 255.960 112.692 ;
      RECT 0.054 112.764 255.960 112.788 ;
      RECT 0.054 112.860 255.960 112.884 ;
      RECT 0.054 112.956 255.960 112.980 ;
      RECT 0.054 113.052 255.960 113.076 ;
      RECT 0.054 113.148 255.960 113.172 ;
      RECT 0.054 113.244 255.960 113.268 ;
      RECT 0.054 113.340 255.960 113.364 ;
      RECT 0.054 113.436 255.960 113.460 ;
      RECT 0.054 113.532 255.960 113.556 ;
      RECT 0.054 113.628 255.960 113.652 ;
      RECT 0.054 113.724 255.960 113.748 ;
      RECT 0.054 113.820 255.960 113.844 ;
      RECT 0.054 113.916 255.960 113.940 ;
      RECT 0.054 114.012 255.960 114.036 ;
      RECT 0.054 114.108 255.960 114.132 ;
      RECT 0.054 114.204 255.960 114.228 ;
      RECT 0.054 114.300 255.960 114.324 ;
      RECT 0.054 114.396 255.960 114.420 ;
      RECT 0.054 114.492 255.960 114.516 ;
      RECT 0.054 114.588 255.960 114.612 ;
      RECT 0.054 114.684 255.960 114.708 ;
      RECT 0.054 114.780 255.960 114.804 ;
      RECT 0.054 114.876 255.960 114.900 ;
      RECT 0.054 114.972 255.960 114.996 ;
      RECT 0.054 115.068 255.960 115.092 ;
      RECT 0.054 115.164 255.960 115.188 ;
      RECT 0.054 115.260 255.960 115.284 ;
      RECT 0.054 115.356 255.960 115.380 ;
      RECT 0.054 115.452 255.960 115.476 ;
      RECT 0.054 115.548 255.960 115.572 ;
      RECT 0.054 115.644 255.960 115.668 ;
      RECT 0.054 115.740 255.960 115.764 ;
      RECT 0.054 115.836 255.960 115.860 ;
      RECT 0.054 115.932 255.960 115.956 ;
      RECT 0.054 116.028 255.960 116.052 ;
      RECT 0.054 116.124 255.960 116.148 ;
      RECT 0.054 116.220 255.960 116.244 ;
      RECT 0.054 116.316 255.960 116.340 ;
      RECT 0.054 116.412 255.960 116.436 ;
      RECT 0.054 116.508 255.960 116.532 ;
      RECT 0.054 116.604 255.960 116.628 ;
      RECT 0.054 116.700 255.960 116.724 ;
      RECT 0.054 116.796 255.960 116.820 ;
      RECT 0.054 116.892 255.960 116.916 ;
      RECT 0.054 116.988 255.960 117.012 ;
      RECT 0.054 117.084 255.960 117.108 ;
      RECT 0.054 117.180 255.960 117.204 ;
      RECT 0.054 117.276 255.960 117.300 ;
      RECT 0.054 117.372 255.960 117.396 ;
      RECT 0.054 117.468 255.960 117.492 ;
      RECT 0.054 117.564 255.960 117.588 ;
      RECT 0.054 117.660 255.960 117.684 ;
      RECT 0.054 117.756 255.960 117.780 ;
      RECT 0.054 117.852 255.960 117.876 ;
      RECT 0.054 117.948 255.960 117.972 ;
      RECT 0.054 118.044 255.960 118.068 ;
      RECT 0.054 118.140 255.960 118.164 ;
      RECT 0.054 118.236 255.960 118.260 ;
      RECT 0.054 118.332 255.960 118.356 ;
      RECT 0.054 118.428 255.960 118.452 ;
      RECT 0.054 118.524 255.960 118.548 ;
      RECT 0.054 118.620 255.960 118.644 ;
      RECT 0.054 118.716 255.960 118.740 ;
      RECT 0.054 118.812 255.960 118.836 ;
      RECT 0.054 118.908 255.960 118.932 ;
      RECT 0.054 119.004 255.960 119.028 ;
      RECT 0.054 119.100 255.960 119.124 ;
      RECT 0.054 119.196 255.960 119.220 ;
      RECT 0.054 119.292 255.960 119.316 ;
      RECT 0.054 119.388 255.960 119.412 ;
      RECT 0.054 119.484 255.960 119.508 ;
      RECT 0.054 119.580 255.960 119.604 ;
      RECT 0.054 119.676 255.960 119.700 ;
      RECT 0.054 119.772 255.960 119.796 ;
      RECT 0.054 119.868 255.960 119.892 ;
      RECT 0.054 119.964 255.960 119.988 ;
      RECT 0.054 120.060 255.960 120.084 ;
      RECT 0.054 120.156 255.960 120.180 ;
      RECT 0.054 120.252 255.960 120.276 ;
      RECT 0.054 120.348 255.960 120.372 ;
      RECT 0.054 120.444 255.960 120.468 ;
      RECT 0.054 120.540 255.960 120.564 ;
      RECT 0.054 120.636 255.960 120.660 ;
      RECT 0.054 120.732 255.960 120.756 ;
      RECT 0.054 120.828 255.960 120.852 ;
      RECT 0.054 120.924 255.960 120.948 ;
      RECT 0.054 121.020 255.960 121.044 ;
      RECT 0.054 121.116 255.960 121.140 ;
      RECT 0.054 121.212 255.960 121.236 ;
      RECT 0.054 121.308 255.960 121.332 ;
      RECT 0.054 121.404 255.960 121.428 ;
      RECT 0.054 121.500 255.960 121.524 ;
      RECT 0.054 121.596 255.960 121.620 ;
      RECT 0.054 121.692 255.960 121.716 ;
      RECT 0.054 121.788 255.960 121.812 ;
      RECT 0.054 121.884 255.960 121.908 ;
      RECT 0.054 121.980 255.960 122.004 ;
      RECT 0.054 122.076 255.960 122.100 ;
      RECT 0.054 122.172 255.960 122.196 ;
      RECT 0.054 122.268 255.960 122.292 ;
      RECT 0.054 122.364 255.960 122.388 ;
      RECT 0.054 122.460 255.960 122.484 ;
      RECT 0.054 122.556 255.960 122.580 ;
      RECT 0.054 122.652 255.960 122.676 ;
      RECT 0.054 122.748 255.960 122.772 ;
      RECT 0.054 122.844 255.960 122.868 ;
      RECT 0.054 122.940 255.960 122.964 ;
      RECT 0.054 123.036 255.960 123.060 ;
      RECT 0.054 123.132 255.960 123.156 ;
      RECT 0.054 123.228 255.960 123.252 ;
      RECT 0.054 123.324 255.960 123.348 ;
      RECT 0.054 123.420 255.960 123.444 ;
      RECT 0.054 123.516 255.960 123.540 ;
      RECT 0.054 123.612 255.960 123.636 ;
      RECT 0.054 123.708 255.960 123.732 ;
      RECT 0.054 123.804 255.960 123.828 ;
      RECT 0.054 123.900 255.960 123.924 ;
      RECT 0.054 123.996 255.960 124.020 ;
      RECT 0.054 124.092 255.960 124.116 ;
      RECT 0.054 124.188 255.960 124.212 ;
      RECT 0.054 124.284 255.960 124.308 ;
      RECT 0.054 124.380 255.960 124.404 ;
      RECT 0.054 124.476 255.960 124.500 ;
      RECT 0.054 124.572 255.960 124.596 ;
      RECT 0.054 124.668 255.960 124.692 ;
      RECT 0.054 124.764 255.960 124.788 ;
      RECT 0.054 124.860 255.960 124.884 ;
      RECT 0.054 124.956 255.960 124.980 ;
      RECT 0.054 125.052 255.960 125.076 ;
      RECT 0.054 125.148 255.960 125.172 ;
      RECT 0.054 125.244 255.960 125.268 ;
      RECT 0.054 125.340 255.960 125.364 ;
      RECT 0.054 125.436 255.960 125.460 ;
      RECT 0.054 125.532 255.960 125.556 ;
      RECT 0.054 125.628 255.960 125.652 ;
      RECT 0.054 125.724 255.960 125.748 ;
      RECT 0.054 125.820 255.960 125.844 ;
      RECT 0.054 125.916 255.960 125.940 ;
      RECT 0.054 126.012 255.960 126.036 ;
      RECT 0.054 126.108 255.960 126.132 ;
      RECT 0.054 126.204 255.960 126.228 ;
      RECT 0.054 126.300 255.960 126.324 ;
      RECT 0.054 126.396 255.960 126.420 ;
      RECT 0.054 126.492 255.960 126.516 ;
      RECT 0.054 126.588 255.960 126.612 ;
      RECT 0.054 126.684 255.960 126.708 ;
      RECT 0.054 126.780 255.960 126.804 ;
      RECT 0.054 126.876 255.960 126.900 ;
      RECT 0.054 126.972 255.960 126.996 ;
      RECT 0.054 127.068 255.960 127.092 ;
      RECT 0.054 127.164 255.960 127.188 ;
      RECT 0.054 127.260 255.960 127.284 ;
      RECT 0.054 127.356 255.960 127.380 ;
      RECT 0.054 127.452 255.960 127.476 ;
      RECT 0.054 127.548 255.960 127.572 ;
      RECT 0.054 127.644 255.960 127.668 ;
      RECT 0.054 127.740 255.960 127.764 ;
      RECT 0.054 127.836 255.960 127.860 ;
      RECT 0.054 127.932 255.960 127.956 ;
      RECT 0.054 128.028 255.960 128.052 ;
      RECT 0.054 128.124 255.960 128.148 ;
      RECT 0.054 128.220 255.960 128.244 ;
    END
  END VSS
  OBS
    LAYER M1 ;
      RECT 0.000 0.000 256.014 128.250 ;
    LAYER M2 ;
      RECT 0.000 0.000 256.014 128.250 ;
    LAYER M3 ;
      RECT 0.000 0.000 256.014 128.250 ;
  END
END fakeram7_4096x16
END LIBRARY
